VERSION 5.8 ;
BUSBITCHARS "[]" ;
DIVIDERCHAR "/" ;
CLEARANCEMEASURE EUCLIDEAN ;

SITE coresite
    SIZE 0.0450 BY 0.1440 ;
    CLASS CORE ;
    SYMMETRY X Y ;
END coresite

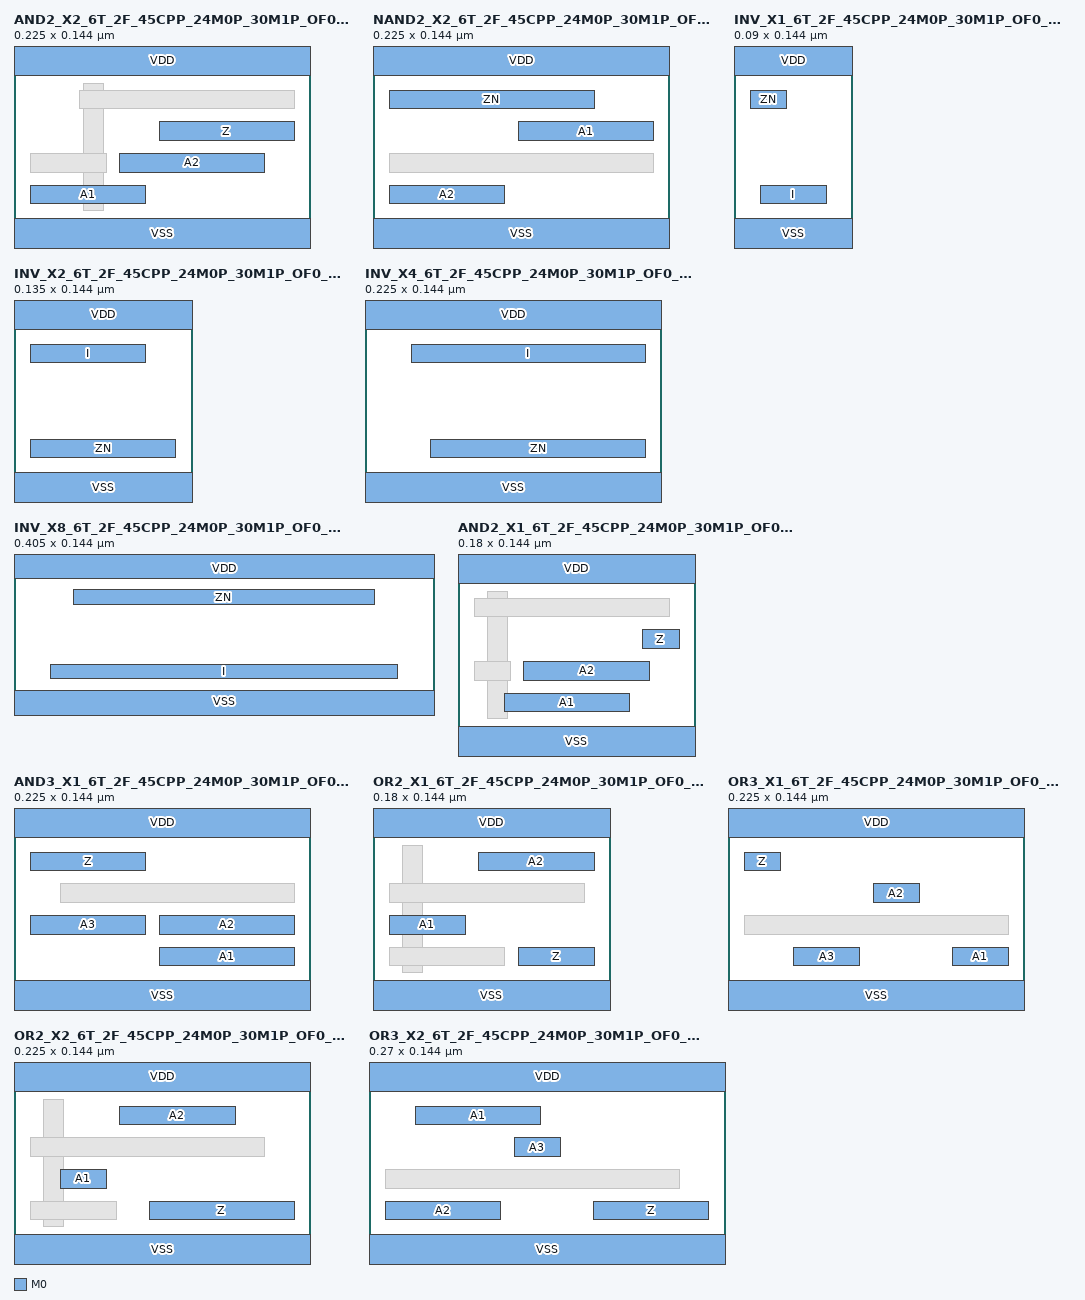
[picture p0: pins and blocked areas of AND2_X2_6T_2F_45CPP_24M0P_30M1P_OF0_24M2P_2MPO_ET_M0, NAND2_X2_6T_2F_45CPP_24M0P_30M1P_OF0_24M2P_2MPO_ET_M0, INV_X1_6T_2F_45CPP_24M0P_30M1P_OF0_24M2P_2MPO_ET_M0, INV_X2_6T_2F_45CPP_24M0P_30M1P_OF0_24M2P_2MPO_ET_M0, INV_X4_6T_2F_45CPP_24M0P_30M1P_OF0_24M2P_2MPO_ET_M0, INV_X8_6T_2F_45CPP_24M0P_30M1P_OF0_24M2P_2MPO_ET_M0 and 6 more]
MACRO AND2_X2_6T_2F_45CPP_24M0P_30M1P_OF0_24M2P_2MPO_ET_M0
  CLASS CORE ;
  ORIGIN 0 0 ;
  FOREIGN AND2_X2_6T_2F_45CPP_24M0P_30M1P_OF0_24M2P_2MPO_ET_M0 0 0 ;
  SIZE 0.2250 BY 0.1440 ;
  SYMMETRY X Y ;
  SITE coresite ;
  PIN A2
    DIRECTION INPUT ;
    USE SIGNAL ;
    PORT
      LAYER M0 ;
        RECT 0.0800 0.0670 0.1900 0.0530 ;
    END
  END A2
  PIN A1
    DIRECTION INPUT ;
    USE SIGNAL ;
    PORT
      LAYER M0 ;
        RECT 0.0125 0.0430 0.1000 0.0290 ;
    END
  END A1
  PIN Z
    DIRECTION OUTPUT ;
    USE SIGNAL ;
    PORT
      LAYER M0 ;
        RECT 0.1100 0.0910 0.2125 0.0770 ;
    END
  END Z
  PIN VDD
    DIRECTION INOUT ;
    USE POWER ;
    SHAPE ABUTMENT ;
    PORT
      LAYER M0 ;
        RECT 0.0000 0.1260 0.2250 0.1620 ;
    END
  END VDD
  PIN VSS
    DIRECTION INOUT ;
    USE GROUND ;
    SHAPE ABUTMENT ;
    PORT
      LAYER M0 ;
        RECT 0.0000 -0.0180 0.2250 0.0180 ;
    END
  END VSS
  OBS
      LAYER V0 ;
        RECT 0.0530 0.0530 0.0670 0.0670 ;
        RECT 0.0530 0.1010 0.0670 0.1150 ;
      LAYER M1 ;
        RECT 0.0525 0.1200 0.0675 0.0240 ;
      LAYER M0 ;
        RECT 0.0500 0.1010 0.2125 0.1150 ;
        RECT 0.0125 0.0530 0.0700 0.0670 ;
  END
END AND2_X2_6T_2F_45CPP_24M0P_30M1P_OF0_24M2P_2MPO_ET_M0

MACRO NAND2_X2_6T_2F_45CPP_24M0P_30M1P_OF0_24M2P_2MPO_ET_M0
  CLASS CORE ;
  ORIGIN 0 0 ;
  FOREIGN NAND2_X2_6T_2F_45CPP_24M0P_30M1P_OF0_24M2P_2MPO_ET_M0 0 0 ;
  SIZE 0.2250 BY 0.1440 ;
  SYMMETRY X Y ;
  SITE coresite ;
  PIN ZN
    DIRECTION OUTPUT ;
    USE SIGNAL ;
    PORT
      LAYER M0 ;
        RECT 0.0125 0.1150 0.1675 0.1010 ;
    END
  END ZN
  PIN A2
    DIRECTION INPUT ;
    USE SIGNAL ;
    PORT
      LAYER M0 ;
        RECT 0.0125 0.0430 0.1000 0.0290 ;
    END
  END A2
  PIN A1
    DIRECTION INPUT ;
    USE SIGNAL ;
    PORT
      LAYER M0 ;
        RECT 0.1100 0.0910 0.2125 0.0770 ;
    END
  END A1
  PIN VDD
    DIRECTION INOUT ;
    USE POWER ;
    SHAPE ABUTMENT ;
    PORT
      LAYER M0 ;
        RECT 0.0000 0.1260 0.2250 0.1620 ;
    END
  END VDD
  PIN VSS
    DIRECTION INOUT ;
    USE GROUND ;
    SHAPE ABUTMENT ;
    PORT
      LAYER M0 ;
        RECT 0.0000 -0.0180 0.2250 0.0180 ;
    END
  END VSS
  OBS
      LAYER M0 ;
        RECT 0.0125 0.0530 0.2125 0.0670 ;
  END
END NAND2_X2_6T_2F_45CPP_24M0P_30M1P_OF0_24M2P_2MPO_ET_M0

MACRO INV_X1_6T_2F_45CPP_24M0P_30M1P_OF0_24M2P_2MPO_ET_M0
  CLASS CORE ;
  ORIGIN 0 0 ;
  FOREIGN INV_X1_6T_2F_45CPP_24M0P_30M1P_OF0_24M2P_2MPO_ET_M0 0 0 ;
  SIZE 0.0900 BY 0.1440 ;
  SYMMETRY X Y ;
  SITE coresite ;
  PIN ZN
    DIRECTION OUTPUT ;
    USE SIGNAL ;
    PORT
      LAYER M0 ;
        RECT 0.0125 0.1150 0.0400 0.1010 ;
    END
  END ZN
  PIN I
    DIRECTION INPUT ;
    USE SIGNAL ;
    PORT
      LAYER M0 ;
        RECT 0.0200 0.0430 0.0700 0.0290 ;
    END
  END I
  PIN VDD
    DIRECTION INOUT ;
    USE POWER ;
    SHAPE ABUTMENT ;
    PORT
      LAYER M0 ;
        RECT 0.0000 0.1260 0.0900 0.1620 ;
    END
  END VDD
  PIN VSS
    DIRECTION INOUT ;
    USE GROUND ;
    SHAPE ABUTMENT ;
    PORT
      LAYER M0 ;
        RECT 0.0000 -0.0180 0.0900 0.0180 ;
    END
  END VSS
END INV_X1_6T_2F_45CPP_24M0P_30M1P_OF0_24M2P_2MPO_ET_M0

MACRO INV_X2_6T_2F_45CPP_24M0P_30M1P_OF0_24M2P_2MPO_ET_M0
  CLASS CORE ;
  ORIGIN 0 0 ;
  FOREIGN INV_X2_6T_2F_45CPP_24M0P_30M1P_OF0_24M2P_2MPO_ET_M0 0 0 ;
  SIZE 0.1350 BY 0.1440 ;
  SYMMETRY X Y ;
  SITE coresite ;
  PIN I
    DIRECTION INPUT ;
    USE SIGNAL ;
    PORT
      LAYER M0 ;
        RECT 0.0125 0.1150 0.1000 0.1010 ;
    END
  END I
  PIN ZN
    DIRECTION OUTPUT ;
    USE SIGNAL ;
    PORT
      LAYER M0 ;
        RECT 0.0125 0.0430 0.1225 0.0290 ;
    END
  END ZN
  PIN VDD
    DIRECTION INOUT ;
    USE POWER ;
    SHAPE ABUTMENT ;
    PORT
      LAYER M0 ;
        RECT 0.0000 0.1260 0.1350 0.1620 ;
    END
  END VDD
  PIN VSS
    DIRECTION INOUT ;
    USE GROUND ;
    SHAPE ABUTMENT ;
    PORT
      LAYER M0 ;
        RECT 0.0000 -0.0180 0.1350 0.0180 ;
    END
  END VSS
END INV_X2_6T_2F_45CPP_24M0P_30M1P_OF0_24M2P_2MPO_ET_M0

MACRO INV_X4_6T_2F_45CPP_24M0P_30M1P_OF0_24M2P_2MPO_ET_M0
  CLASS CORE ;
  ORIGIN 0 0 ;
  FOREIGN INV_X4_6T_2F_45CPP_24M0P_30M1P_OF0_24M2P_2MPO_ET_M0 0 0 ;
  SIZE 0.2250 BY 0.1440 ;
  SYMMETRY X Y ;
  SITE coresite ;
  PIN I
    DIRECTION INPUT ;
    USE SIGNAL ;
    PORT
      LAYER M0 ;
        RECT 0.0350 0.1150 0.2125 0.1010 ;
    END
  END I
  PIN ZN
    DIRECTION OUTPUT ;
    USE SIGNAL ;
    PORT
      LAYER M0 ;
        RECT 0.0500 0.0430 0.2125 0.0290 ;
    END
  END ZN
  PIN VDD
    DIRECTION INOUT ;
    USE POWER ;
    SHAPE ABUTMENT ;
    PORT
      LAYER M0 ;
        RECT 0.0000 0.1260 0.2250 0.1620 ;
    END
  END VDD
  PIN VSS
    DIRECTION INOUT ;
    USE GROUND ;
    SHAPE ABUTMENT ;
    PORT
      LAYER M0 ;
        RECT 0.0000 -0.0180 0.2250 0.0180 ;
    END
  END VSS
END INV_X4_6T_2F_45CPP_24M0P_30M1P_OF0_24M2P_2MPO_ET_M0

MACRO INV_X8_6T_2F_45CPP_24M0P_30M1P_OF0_24M2P_2MPO_ET_M0
  CLASS CORE ;
  ORIGIN 0 0 ;
  FOREIGN INV_X8_6T_2F_45CPP_24M0P_30M1P_OF0_24M2P_2MPO_ET_M0 0 0 ;
  SIZE 0.4050 BY 0.1440 ;
  SYMMETRY X Y ;
  SITE coresite ;
  PIN ZN
    DIRECTION OUTPUT ;
    USE SIGNAL ;
    PORT
      LAYER M0 ;
        RECT 0.0575 0.1150 0.3475 0.1010 ;
    END
  END ZN
  PIN I
    DIRECTION INPUT ;
    USE SIGNAL ;
    PORT
      LAYER M0 ;
        RECT 0.0350 0.0430 0.3700 0.0290 ;
    END
  END I
  PIN VDD
    DIRECTION INOUT ;
    USE POWER ;
    SHAPE ABUTMENT ;
    PORT
      LAYER M0 ;
        RECT 0.0000 0.1260 0.4050 0.1620 ;
    END
  END VDD
  PIN VSS
    DIRECTION INOUT ;
    USE GROUND ;
    SHAPE ABUTMENT ;
    PORT
      LAYER M0 ;
        RECT 0.0000 -0.0180 0.4050 0.0180 ;
    END
  END VSS
END INV_X8_6T_2F_45CPP_24M0P_30M1P_OF0_24M2P_2MPO_ET_M0

MACRO AND2_X1_6T_2F_45CPP_24M0P_30M1P_OF0_24M2P_2MPO_ET_M0
  CLASS CORE ;
  ORIGIN 0 0 ;
  FOREIGN AND2_X1_6T_2F_45CPP_24M0P_30M1P_OF0_24M2P_2MPO_ET_M0 0 0 ;
  SIZE 0.1800 BY 0.1440 ;
  SYMMETRY X Y ;
  SITE coresite ;
  PIN A2
    DIRECTION INPUT ;
    USE SIGNAL ;
    PORT
      LAYER M0 ;
        RECT 0.0500 0.0670 0.1450 0.0530 ;
    END
  END A2
  PIN A1
    DIRECTION INPUT ;
    USE SIGNAL ;
    PORT
      LAYER M0 ;
        RECT 0.0350 0.0430 0.1300 0.0290 ;
    END
  END A1
  PIN Z
    DIRECTION OUTPUT ;
    USE SIGNAL ;
    PORT
      LAYER M0 ;
        RECT 0.1400 0.0910 0.1675 0.0770 ;
    END
  END Z
  PIN VDD
    DIRECTION INOUT ;
    USE POWER ;
    SHAPE ABUTMENT ;
    PORT
      LAYER M0 ;
        RECT 0.0000 0.1260 0.1800 0.1620 ;
    END
  END VDD
  PIN VSS
    DIRECTION INOUT ;
    USE GROUND ;
    SHAPE ABUTMENT ;
    PORT
      LAYER M0 ;
        RECT 0.0000 -0.0180 0.1800 0.0180 ;
    END
  END VSS
  OBS
      LAYER V0 ;
        RECT 0.0230 0.0530 0.0370 0.0670 ;
        RECT 0.0230 0.1010 0.0370 0.1150 ;
      LAYER M1 ;
        RECT 0.0225 0.1200 0.0375 0.0240 ;
      LAYER M0 ;
        RECT 0.0125 0.1010 0.1600 0.1150 ;
        RECT 0.0125 0.0530 0.0400 0.0670 ;
  END
END AND2_X1_6T_2F_45CPP_24M0P_30M1P_OF0_24M2P_2MPO_ET_M0

MACRO AND3_X1_6T_2F_45CPP_24M0P_30M1P_OF0_24M2P_2MPO_ET_M0
  CLASS CORE ;
  ORIGIN 0 0 ;
  FOREIGN AND3_X1_6T_2F_45CPP_24M0P_30M1P_OF0_24M2P_2MPO_ET_M0 0 0 ;
  SIZE 0.2250 BY 0.1440 ;
  SYMMETRY X Y ;
  SITE coresite ;
  PIN A3
    DIRECTION INPUT ;
    USE SIGNAL ;
    PORT
      LAYER M0 ;
        RECT 0.0125 0.0670 0.1000 0.0530 ;
    END
  END A3
  PIN A2
    DIRECTION INPUT ;
    USE SIGNAL ;
    PORT
      LAYER M0 ;
        RECT 0.1100 0.0670 0.2125 0.0530 ;
    END
  END A2
  PIN Z
    DIRECTION OUTPUT ;
    USE SIGNAL ;
    PORT
      LAYER M0 ;
        RECT 0.0125 0.1150 0.1000 0.1010 ;
    END
  END Z
  PIN A1
    DIRECTION INPUT ;
    USE SIGNAL ;
    PORT
      LAYER M0 ;
        RECT 0.1100 0.0430 0.2125 0.0290 ;
    END
  END A1
  PIN VDD
    DIRECTION INOUT ;
    USE POWER ;
    SHAPE ABUTMENT ;
    PORT
      LAYER M0 ;
        RECT 0.0000 0.1260 0.2250 0.1620 ;
    END
  END VDD
  PIN VSS
    DIRECTION INOUT ;
    USE GROUND ;
    SHAPE ABUTMENT ;
    PORT
      LAYER M0 ;
        RECT 0.0000 -0.0180 0.2250 0.0180 ;
    END
  END VSS
  OBS
      LAYER M0 ;
        RECT 0.0350 0.0770 0.2125 0.0910 ;
  END
END AND3_X1_6T_2F_45CPP_24M0P_30M1P_OF0_24M2P_2MPO_ET_M0

MACRO OR2_X1_6T_2F_45CPP_24M0P_30M1P_OF0_24M2P_2MPO_ET_M0
  CLASS CORE ;
  ORIGIN 0 0 ;
  FOREIGN OR2_X1_6T_2F_45CPP_24M0P_30M1P_OF0_24M2P_2MPO_ET_M0 0 0 ;
  SIZE 0.1800 BY 0.1440 ;
  SYMMETRY X Y ;
  SITE coresite ;
  PIN A1
    DIRECTION INPUT ;
    USE SIGNAL ;
    PORT
      LAYER M0 ;
        RECT 0.0125 0.0670 0.0700 0.0530 ;
    END
  END A1
  PIN A2
    DIRECTION INPUT ;
    USE SIGNAL ;
    PORT
      LAYER M0 ;
        RECT 0.0800 0.1150 0.1675 0.1010 ;
    END
  END A2
  PIN Z
    DIRECTION OUTPUT ;
    USE SIGNAL ;
    PORT
      LAYER M0 ;
        RECT 0.1100 0.0430 0.1675 0.0290 ;
    END
  END Z
  PIN VDD
    DIRECTION INOUT ;
    USE POWER ;
    SHAPE ABUTMENT ;
    PORT
      LAYER M0 ;
        RECT 0.0000 0.1260 0.1800 0.1620 ;
    END
  END VDD
  PIN VSS
    DIRECTION INOUT ;
    USE GROUND ;
    SHAPE ABUTMENT ;
    PORT
      LAYER M0 ;
        RECT 0.0000 -0.0180 0.1800 0.0180 ;
    END
  END VSS
  OBS
      LAYER V0 ;
        RECT 0.0230 0.0290 0.0370 0.0430 ;
        RECT 0.0230 0.0770 0.0370 0.0910 ;
      LAYER M1 ;
        RECT 0.0225 0.1200 0.0375 0.0240 ;
      LAYER M0 ;
        RECT 0.0125 0.0770 0.1600 0.0910 ;
        RECT 0.0125 0.0290 0.1000 0.0430 ;
  END
END OR2_X1_6T_2F_45CPP_24M0P_30M1P_OF0_24M2P_2MPO_ET_M0

MACRO OR3_X1_6T_2F_45CPP_24M0P_30M1P_OF0_24M2P_2MPO_ET_M0
  CLASS CORE ;
  ORIGIN 0 0 ;
  FOREIGN OR3_X1_6T_2F_45CPP_24M0P_30M1P_OF0_24M2P_2MPO_ET_M0 0 0 ;
  SIZE 0.2250 BY 0.1440 ;
  SYMMETRY X Y ;
  SITE coresite ;
  PIN Z
    DIRECTION OUTPUT ;
    USE SIGNAL ;
    PORT
      LAYER M0 ;
        RECT 0.0125 0.1150 0.0400 0.1010 ;
    END
  END Z
  PIN A3
    DIRECTION INPUT ;
    USE SIGNAL ;
    PORT
      LAYER M0 ;
        RECT 0.0500 0.0430 0.1000 0.0290 ;
    END
  END A3
  PIN A2
    DIRECTION INPUT ;
    USE SIGNAL ;
    PORT
      LAYER M0 ;
        RECT 0.1100 0.0910 0.1450 0.0770 ;
    END
  END A2
  PIN A1
    DIRECTION INPUT ;
    USE SIGNAL ;
    PORT
      LAYER M0 ;
        RECT 0.1700 0.0430 0.2125 0.0290 ;
    END
  END A1
  PIN VDD
    DIRECTION INOUT ;
    USE POWER ;
    SHAPE ABUTMENT ;
    PORT
      LAYER M0 ;
        RECT 0.0000 0.1260 0.2250 0.1620 ;
    END
  END VDD
  PIN VSS
    DIRECTION INOUT ;
    USE GROUND ;
    SHAPE ABUTMENT ;
    PORT
      LAYER M0 ;
        RECT 0.0000 -0.0180 0.2250 0.0180 ;
    END
  END VSS
  OBS
      LAYER M0 ;
        RECT 0.0125 0.0530 0.2125 0.0670 ;
  END
END OR3_X1_6T_2F_45CPP_24M0P_30M1P_OF0_24M2P_2MPO_ET_M0

MACRO OR2_X2_6T_2F_45CPP_24M0P_30M1P_OF0_24M2P_2MPO_ET_M0
  CLASS CORE ;
  ORIGIN 0 0 ;
  FOREIGN OR2_X2_6T_2F_45CPP_24M0P_30M1P_OF0_24M2P_2MPO_ET_M0 0 0 ;
  SIZE 0.2250 BY 0.1440 ;
  SYMMETRY X Y ;
  SITE coresite ;
  PIN A1
    DIRECTION INPUT ;
    USE SIGNAL ;
    PORT
      LAYER M0 ;
        RECT 0.0350 0.0670 0.0700 0.0530 ;
    END
  END A1
  PIN A2
    DIRECTION INPUT ;
    USE SIGNAL ;
    PORT
      LAYER M0 ;
        RECT 0.0800 0.1150 0.1675 0.1010 ;
    END
  END A2
  PIN Z
    DIRECTION OUTPUT ;
    USE SIGNAL ;
    PORT
      LAYER M0 ;
        RECT 0.1025 0.0430 0.2125 0.0290 ;
    END
  END Z
  PIN VDD
    DIRECTION INOUT ;
    USE POWER ;
    SHAPE ABUTMENT ;
    PORT
      LAYER M0 ;
        RECT 0.0000 0.1260 0.2250 0.1620 ;
    END
  END VDD
  PIN VSS
    DIRECTION INOUT ;
    USE GROUND ;
    SHAPE ABUTMENT ;
    PORT
      LAYER M0 ;
        RECT 0.0000 -0.0180 0.2250 0.0180 ;
    END
  END VSS
  OBS
      LAYER V0 ;
        RECT 0.0230 0.0290 0.0370 0.0430 ;
        RECT 0.0230 0.0770 0.0370 0.0910 ;
      LAYER M1 ;
        RECT 0.0225 0.1200 0.0375 0.0240 ;
      LAYER M0 ;
        RECT 0.0125 0.0770 0.1900 0.0910 ;
        RECT 0.0125 0.0290 0.0775 0.0430 ;
  END
END OR2_X2_6T_2F_45CPP_24M0P_30M1P_OF0_24M2P_2MPO_ET_M0

MACRO OR3_X2_6T_2F_45CPP_24M0P_30M1P_OF0_24M2P_2MPO_ET_M0
  CLASS CORE ;
  ORIGIN 0 0 ;
  FOREIGN OR3_X2_6T_2F_45CPP_24M0P_30M1P_OF0_24M2P_2MPO_ET_M0 0 0 ;
  SIZE 0.2700 BY 0.1440 ;
  SYMMETRY X Y ;
  SITE coresite ;
  PIN A1
    DIRECTION INPUT ;
    USE SIGNAL ;
    PORT
      LAYER M0 ;
        RECT 0.0350 0.1150 0.1300 0.1010 ;
    END
  END A1
  PIN A2
    DIRECTION INPUT ;
    USE SIGNAL ;
    PORT
      LAYER M0 ;
        RECT 0.0125 0.0430 0.1000 0.0290 ;
    END
  END A2
  PIN A3
    DIRECTION INPUT ;
    USE SIGNAL ;
    PORT
      LAYER M0 ;
        RECT 0.1100 0.0910 0.1450 0.0770 ;
    END
  END A3
  PIN Z
    DIRECTION OUTPUT ;
    USE SIGNAL ;
    PORT
      LAYER M0 ;
        RECT 0.1700 0.0430 0.2575 0.0290 ;
    END
  END Z
  PIN VDD
    DIRECTION INOUT ;
    USE POWER ;
    SHAPE ABUTMENT ;
    PORT
      LAYER M0 ;
        RECT 0.0000 0.1260 0.2700 0.1620 ;
    END
  END VDD
  PIN VSS
    DIRECTION INOUT ;
    USE GROUND ;
    SHAPE ABUTMENT ;
    PORT
      LAYER M0 ;
        RECT 0.0000 -0.0180 0.2700 0.0180 ;
    END
  END VSS
  OBS
      LAYER M0 ;
        RECT 0.0125 0.0530 0.2350 0.0670 ;
  END
END OR3_X2_6T_2F_45CPP_24M0P_30M1P_OF0_24M2P_2MPO_ET_M0

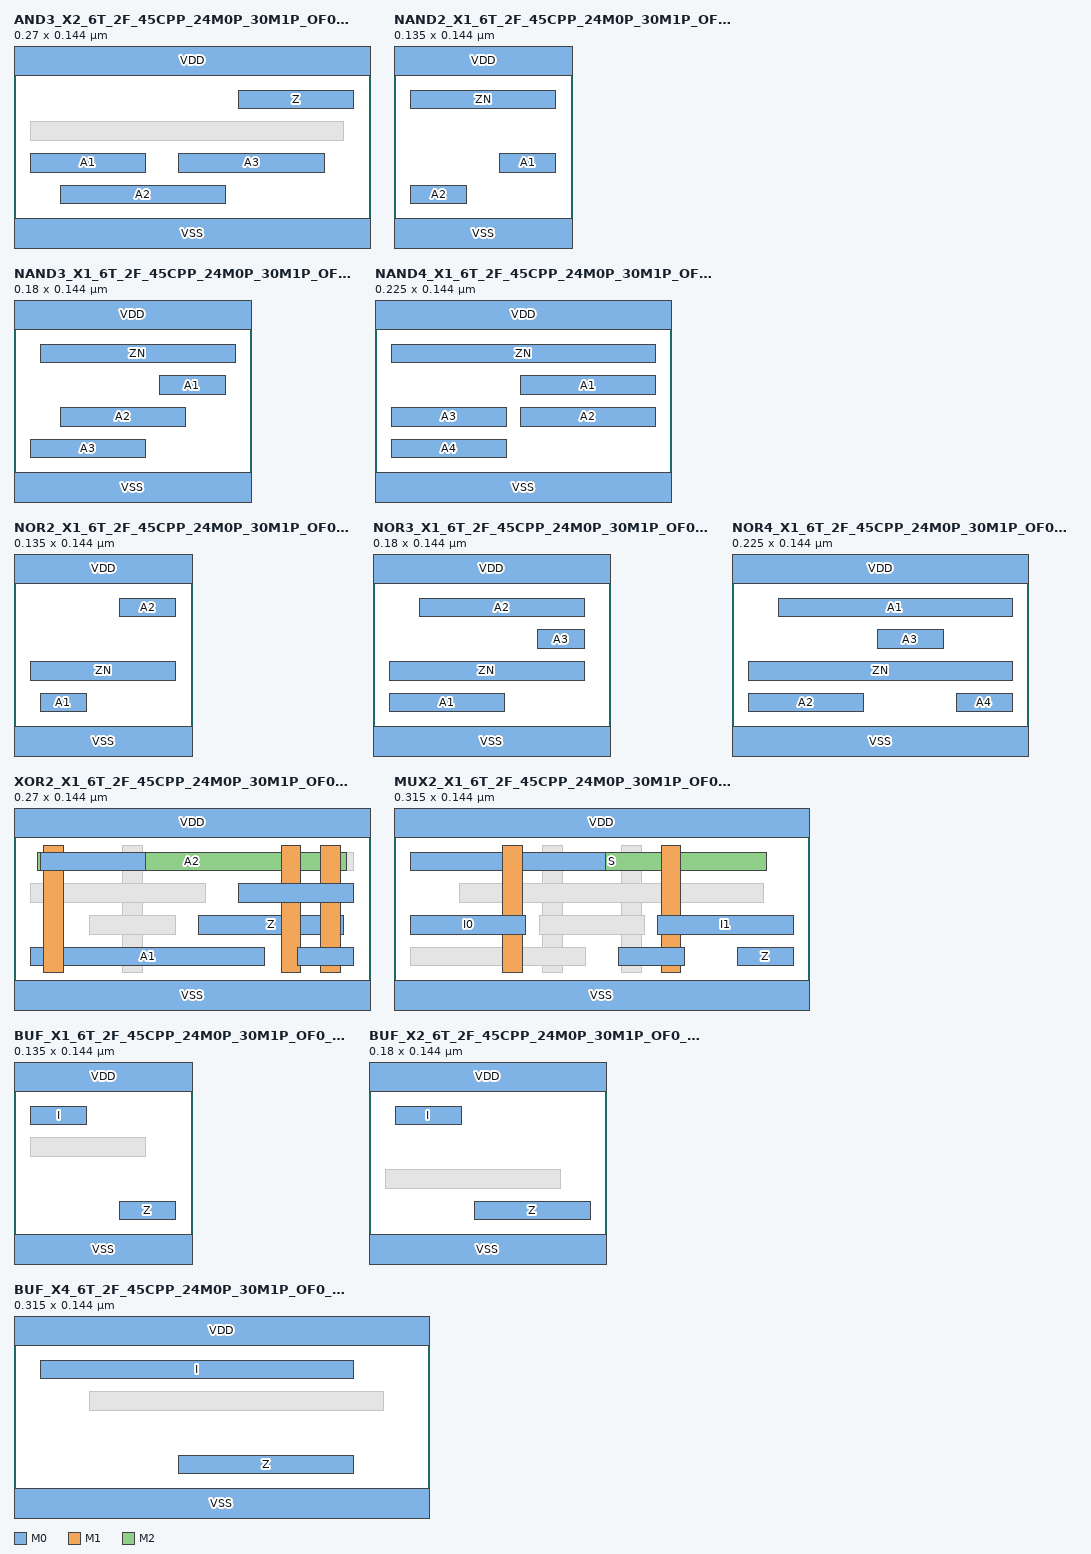
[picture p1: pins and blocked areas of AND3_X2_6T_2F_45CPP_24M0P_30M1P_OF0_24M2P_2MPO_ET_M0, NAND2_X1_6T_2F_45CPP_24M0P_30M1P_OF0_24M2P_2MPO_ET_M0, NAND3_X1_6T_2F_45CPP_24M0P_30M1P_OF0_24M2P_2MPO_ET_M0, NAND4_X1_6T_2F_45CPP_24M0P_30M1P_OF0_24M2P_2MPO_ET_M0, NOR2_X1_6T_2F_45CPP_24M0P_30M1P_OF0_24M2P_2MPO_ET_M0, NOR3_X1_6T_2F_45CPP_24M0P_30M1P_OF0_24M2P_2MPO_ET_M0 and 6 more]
MACRO AND3_X2_6T_2F_45CPP_24M0P_30M1P_OF0_24M2P_2MPO_ET_M0
  CLASS CORE ;
  ORIGIN 0 0 ;
  FOREIGN AND3_X2_6T_2F_45CPP_24M0P_30M1P_OF0_24M2P_2MPO_ET_M0 0 0 ;
  SIZE 0.2700 BY 0.1440 ;
  SYMMETRY X Y ;
  SITE coresite ;
  PIN A1
    DIRECTION INPUT ;
    USE SIGNAL ;
    PORT
      LAYER M0 ;
        RECT 0.0125 0.0670 0.1000 0.0530 ;
    END
  END A1
  PIN A3
    DIRECTION INPUT ;
    USE SIGNAL ;
    PORT
      LAYER M0 ;
        RECT 0.1250 0.0670 0.2350 0.0530 ;
    END
  END A3
  PIN A2
    DIRECTION INPUT ;
    USE SIGNAL ;
    PORT
      LAYER M0 ;
        RECT 0.0350 0.0430 0.1600 0.0290 ;
    END
  END A2
  PIN Z
    DIRECTION OUTPUT ;
    USE SIGNAL ;
    PORT
      LAYER M0 ;
        RECT 0.1700 0.1150 0.2575 0.1010 ;
    END
  END Z
  PIN VDD
    DIRECTION INOUT ;
    USE POWER ;
    SHAPE ABUTMENT ;
    PORT
      LAYER M0 ;
        RECT 0.0000 0.1260 0.2700 0.1620 ;
    END
  END VDD
  PIN VSS
    DIRECTION INOUT ;
    USE GROUND ;
    SHAPE ABUTMENT ;
    PORT
      LAYER M0 ;
        RECT 0.0000 -0.0180 0.2700 0.0180 ;
    END
  END VSS
  OBS
      LAYER M0 ;
        RECT 0.0125 0.0770 0.2500 0.0910 ;
  END
END AND3_X2_6T_2F_45CPP_24M0P_30M1P_OF0_24M2P_2MPO_ET_M0

MACRO NAND2_X1_6T_2F_45CPP_24M0P_30M1P_OF0_24M2P_2MPO_ET_M0
  CLASS CORE ;
  ORIGIN 0 0 ;
  FOREIGN NAND2_X1_6T_2F_45CPP_24M0P_30M1P_OF0_24M2P_2MPO_ET_M0 0 0 ;
  SIZE 0.1350 BY 0.1440 ;
  SYMMETRY X Y ;
  SITE coresite ;
  PIN ZN
    DIRECTION OUTPUT ;
    USE SIGNAL ;
    PORT
      LAYER M0 ;
        RECT 0.0125 0.1150 0.1225 0.1010 ;
    END
  END ZN
  PIN A2
    DIRECTION INPUT ;
    USE SIGNAL ;
    PORT
      LAYER M0 ;
        RECT 0.0125 0.0430 0.0550 0.0290 ;
    END
  END A2
  PIN A1
    DIRECTION INPUT ;
    USE SIGNAL ;
    PORT
      LAYER M0 ;
        RECT 0.0800 0.0670 0.1225 0.0530 ;
    END
  END A1
  PIN VDD
    DIRECTION INOUT ;
    USE POWER ;
    SHAPE ABUTMENT ;
    PORT
      LAYER M0 ;
        RECT 0.0000 0.1260 0.1350 0.1620 ;
    END
  END VDD
  PIN VSS
    DIRECTION INOUT ;
    USE GROUND ;
    SHAPE ABUTMENT ;
    PORT
      LAYER M0 ;
        RECT 0.0000 -0.0180 0.1350 0.0180 ;
    END
  END VSS
END NAND2_X1_6T_2F_45CPP_24M0P_30M1P_OF0_24M2P_2MPO_ET_M0

MACRO NAND3_X1_6T_2F_45CPP_24M0P_30M1P_OF0_24M2P_2MPO_ET_M0
  CLASS CORE ;
  ORIGIN 0 0 ;
  FOREIGN NAND3_X1_6T_2F_45CPP_24M0P_30M1P_OF0_24M2P_2MPO_ET_M0 0 0 ;
  SIZE 0.1800 BY 0.1440 ;
  SYMMETRY X Y ;
  SITE coresite ;
  PIN ZN
    DIRECTION OUTPUT ;
    USE SIGNAL ;
    PORT
      LAYER M0 ;
        RECT 0.0200 0.1150 0.1675 0.1010 ;
    END
  END ZN
  PIN A2
    DIRECTION INPUT ;
    USE SIGNAL ;
    PORT
      LAYER M0 ;
        RECT 0.0350 0.0670 0.1300 0.0530 ;
    END
  END A2
  PIN A3
    DIRECTION INPUT ;
    USE SIGNAL ;
    PORT
      LAYER M0 ;
        RECT 0.0125 0.0430 0.1000 0.0290 ;
    END
  END A3
  PIN A1
    DIRECTION INPUT ;
    USE SIGNAL ;
    PORT
      LAYER M0 ;
        RECT 0.1100 0.0910 0.1600 0.0770 ;
    END
  END A1
  PIN VDD
    DIRECTION INOUT ;
    USE POWER ;
    SHAPE ABUTMENT ;
    PORT
      LAYER M0 ;
        RECT 0.0000 0.1260 0.1800 0.1620 ;
    END
  END VDD
  PIN VSS
    DIRECTION INOUT ;
    USE GROUND ;
    SHAPE ABUTMENT ;
    PORT
      LAYER M0 ;
        RECT 0.0000 -0.0180 0.1800 0.0180 ;
    END
  END VSS
END NAND3_X1_6T_2F_45CPP_24M0P_30M1P_OF0_24M2P_2MPO_ET_M0

MACRO NAND4_X1_6T_2F_45CPP_24M0P_30M1P_OF0_24M2P_2MPO_ET_M0
  CLASS CORE ;
  ORIGIN 0 0 ;
  FOREIGN NAND4_X1_6T_2F_45CPP_24M0P_30M1P_OF0_24M2P_2MPO_ET_M0 0 0 ;
  SIZE 0.2250 BY 0.1440 ;
  SYMMETRY X Y ;
  SITE coresite ;
  PIN ZN
    DIRECTION OUTPUT ;
    USE SIGNAL ;
    PORT
      LAYER M0 ;
        RECT 0.0125 0.1150 0.2125 0.1010 ;
    END
  END ZN
  PIN A3
    DIRECTION INPUT ;
    USE SIGNAL ;
    PORT
      LAYER M0 ;
        RECT 0.0125 0.0670 0.1000 0.0530 ;
    END
  END A3
  PIN A2
    DIRECTION INPUT ;
    USE SIGNAL ;
    PORT
      LAYER M0 ;
        RECT 0.1100 0.0670 0.2125 0.0530 ;
    END
  END A2
  PIN A4
    DIRECTION INPUT ;
    USE SIGNAL ;
    PORT
      LAYER M0 ;
        RECT 0.0125 0.0430 0.1000 0.0290 ;
    END
  END A4
  PIN A1
    DIRECTION INPUT ;
    USE SIGNAL ;
    PORT
      LAYER M0 ;
        RECT 0.1100 0.0910 0.2125 0.0770 ;
    END
  END A1
  PIN VDD
    DIRECTION INOUT ;
    USE POWER ;
    SHAPE ABUTMENT ;
    PORT
      LAYER M0 ;
        RECT 0.0000 0.1260 0.2250 0.1620 ;
    END
  END VDD
  PIN VSS
    DIRECTION INOUT ;
    USE GROUND ;
    SHAPE ABUTMENT ;
    PORT
      LAYER M0 ;
        RECT 0.0000 -0.0180 0.2250 0.0180 ;
    END
  END VSS
END NAND4_X1_6T_2F_45CPP_24M0P_30M1P_OF0_24M2P_2MPO_ET_M0

MACRO NOR2_X1_6T_2F_45CPP_24M0P_30M1P_OF0_24M2P_2MPO_ET_M0
  CLASS CORE ;
  ORIGIN 0 0 ;
  FOREIGN NOR2_X1_6T_2F_45CPP_24M0P_30M1P_OF0_24M2P_2MPO_ET_M0 0 0 ;
  SIZE 0.1350 BY 0.1440 ;
  SYMMETRY X Y ;
  SITE coresite ;
  PIN ZN
    DIRECTION OUTPUT ;
    USE SIGNAL ;
    PORT
      LAYER M0 ;
        RECT 0.0125 0.0670 0.1225 0.0530 ;
    END
  END ZN
  PIN A1
    DIRECTION INPUT ;
    USE SIGNAL ;
    PORT
      LAYER M0 ;
        RECT 0.0200 0.0430 0.0550 0.0290 ;
    END
  END A1
  PIN A2
    DIRECTION INPUT ;
    USE SIGNAL ;
    PORT
      LAYER M0 ;
        RECT 0.0800 0.1150 0.1225 0.1010 ;
    END
  END A2
  PIN VDD
    DIRECTION INOUT ;
    USE POWER ;
    SHAPE ABUTMENT ;
    PORT
      LAYER M0 ;
        RECT 0.0000 0.1260 0.1350 0.1620 ;
    END
  END VDD
  PIN VSS
    DIRECTION INOUT ;
    USE GROUND ;
    SHAPE ABUTMENT ;
    PORT
      LAYER M0 ;
        RECT 0.0000 -0.0180 0.1350 0.0180 ;
    END
  END VSS
END NOR2_X1_6T_2F_45CPP_24M0P_30M1P_OF0_24M2P_2MPO_ET_M0

MACRO NOR3_X1_6T_2F_45CPP_24M0P_30M1P_OF0_24M2P_2MPO_ET_M0
  CLASS CORE ;
  ORIGIN 0 0 ;
  FOREIGN NOR3_X1_6T_2F_45CPP_24M0P_30M1P_OF0_24M2P_2MPO_ET_M0 0 0 ;
  SIZE 0.1800 BY 0.1440 ;
  SYMMETRY X Y ;
  SITE coresite ;
  PIN A2
    DIRECTION INPUT ;
    USE SIGNAL ;
    PORT
      LAYER M0 ;
        RECT 0.0350 0.1150 0.1600 0.1010 ;
    END
  END A2
  PIN ZN
    DIRECTION OUTPUT ;
    USE SIGNAL ;
    PORT
      LAYER M0 ;
        RECT 0.0125 0.0670 0.1600 0.0530 ;
    END
  END ZN
  PIN A1
    DIRECTION INPUT ;
    USE SIGNAL ;
    PORT
      LAYER M0 ;
        RECT 0.0125 0.0430 0.1000 0.0290 ;
    END
  END A1
  PIN A3
    DIRECTION INPUT ;
    USE SIGNAL ;
    PORT
      LAYER M0 ;
        RECT 0.1250 0.0910 0.1600 0.0770 ;
    END
  END A3
  PIN VDD
    DIRECTION INOUT ;
    USE POWER ;
    SHAPE ABUTMENT ;
    PORT
      LAYER M0 ;
        RECT 0.0000 0.1260 0.1800 0.1620 ;
    END
  END VDD
  PIN VSS
    DIRECTION INOUT ;
    USE GROUND ;
    SHAPE ABUTMENT ;
    PORT
      LAYER M0 ;
        RECT 0.0000 -0.0180 0.1800 0.0180 ;
    END
  END VSS
END NOR3_X1_6T_2F_45CPP_24M0P_30M1P_OF0_24M2P_2MPO_ET_M0

MACRO NOR4_X1_6T_2F_45CPP_24M0P_30M1P_OF0_24M2P_2MPO_ET_M0
  CLASS CORE ;
  ORIGIN 0 0 ;
  FOREIGN NOR4_X1_6T_2F_45CPP_24M0P_30M1P_OF0_24M2P_2MPO_ET_M0 0 0 ;
  SIZE 0.2250 BY 0.1440 ;
  SYMMETRY X Y ;
  SITE coresite ;
  PIN A1
    DIRECTION INPUT ;
    USE SIGNAL ;
    PORT
      LAYER M0 ;
        RECT 0.0350 0.1150 0.2125 0.1010 ;
    END
  END A1
  PIN ZN
    DIRECTION OUTPUT ;
    USE SIGNAL ;
    PORT
      LAYER M0 ;
        RECT 0.0125 0.0670 0.2125 0.0530 ;
    END
  END ZN
  PIN A2
    DIRECTION INPUT ;
    USE SIGNAL ;
    PORT
      LAYER M0 ;
        RECT 0.0125 0.0430 0.1000 0.0290 ;
    END
  END A2
  PIN A3
    DIRECTION INPUT ;
    USE SIGNAL ;
    PORT
      LAYER M0 ;
        RECT 0.1100 0.0910 0.1600 0.0770 ;
    END
  END A3
  PIN A4
    DIRECTION INPUT ;
    USE SIGNAL ;
    PORT
      LAYER M0 ;
        RECT 0.1700 0.0430 0.2125 0.0290 ;
    END
  END A4
  PIN VDD
    DIRECTION INOUT ;
    USE POWER ;
    SHAPE ABUTMENT ;
    PORT
      LAYER M0 ;
        RECT 0.0000 0.1260 0.2250 0.1620 ;
    END
  END VDD
  PIN VSS
    DIRECTION INOUT ;
    USE GROUND ;
    SHAPE ABUTMENT ;
    PORT
      LAYER M0 ;
        RECT 0.0000 -0.0180 0.2250 0.0180 ;
    END
  END VSS
END NOR4_X1_6T_2F_45CPP_24M0P_30M1P_OF0_24M2P_2MPO_ET_M0

MACRO XOR2_X1_6T_2F_45CPP_24M0P_30M1P_OF0_24M2P_2MPO_ET_M0
  CLASS CORE ;
  ORIGIN 0 0 ;
  FOREIGN XOR2_X1_6T_2F_45CPP_24M0P_30M1P_OF0_24M2P_2MPO_ET_M0 0 0 ;
  SIZE 0.2700 BY 0.1440 ;
  SYMMETRY X Y ;
  SITE coresite ;
  PIN Z
    DIRECTION OUTPUT ;
    USE SIGNAL ;
    PORT
      LAYER M1 ;
        RECT 0.2025 0.1200 0.2175 0.0240 ;
      LAYER M0 ;
        RECT 0.1700 0.0910 0.2575 0.0770 ;
        RECT 0.1400 0.0670 0.2500 0.0530 ;
    END
  END Z
  PIN A2
    DIRECTION INPUT ;
    USE SIGNAL ;
    PORT
      LAYER M2 ;
        RECT 0.0180 0.1150 0.2520 0.1010 ;
      LAYER M1 ;
        RECT 0.0225 0.1200 0.0375 0.0240 ;
        RECT 0.2325 0.1200 0.2475 0.0240 ;
      LAYER M0 ;
        RECT 0.0200 0.1150 0.1000 0.1010 ;
        RECT 0.2150 0.0430 0.2575 0.0290 ;
    END
  END A2
  PIN A1
    DIRECTION INPUT ;
    USE SIGNAL ;
    PORT
      LAYER M0 ;
        RECT 0.0125 0.0430 0.1900 0.0290 ;
    END
  END A1
  PIN VDD
    DIRECTION INOUT ;
    USE POWER ;
    SHAPE ABUTMENT ;
    PORT
      LAYER M0 ;
        RECT 0.0000 0.1260 0.2700 0.1620 ;
    END
  END VDD
  PIN VSS
    DIRECTION INOUT ;
    USE GROUND ;
    SHAPE ABUTMENT ;
    PORT
      LAYER M0 ;
        RECT 0.0000 -0.0180 0.2700 0.0180 ;
    END
  END VSS
  OBS
      LAYER V0 ;
        RECT 0.2330 0.0290 0.2470 0.0430 ;
        RECT 0.2030 0.0530 0.2170 0.0670 ;
        RECT 0.0830 0.0530 0.0970 0.0670 ;
        RECT 0.2030 0.0770 0.2170 0.0910 ;
        RECT 0.0830 0.0770 0.0970 0.0910 ;
        RECT 0.0230 0.1010 0.0370 0.1150 ;
      LAYER M1 ;
        RECT 0.0825 0.1200 0.0975 0.0240 ;
      LAYER M0 ;
        RECT 0.1100 0.1010 0.2575 0.1150 ;
        RECT 0.0125 0.0770 0.1450 0.0910 ;
        RECT 0.0575 0.0530 0.1225 0.0670 ;
      LAYER V1 ;
        RECT 0.2330 0.1010 0.2470 0.1150 ;
        RECT 0.0230 0.1010 0.0370 0.1150 ;
  END
END XOR2_X1_6T_2F_45CPP_24M0P_30M1P_OF0_24M2P_2MPO_ET_M0

MACRO MUX2_X1_6T_2F_45CPP_24M0P_30M1P_OF0_24M2P_2MPO_ET_M0
  CLASS CORE ;
  ORIGIN 0 0 ;
  FOREIGN MUX2_X1_6T_2F_45CPP_24M0P_30M1P_OF0_24M2P_2MPO_ET_M0 0 0 ;
  SIZE 0.3150 BY 0.1440 ;
  SYMMETRY X Y ;
  SITE coresite ;
  PIN S
    DIRECTION INPUT ;
    USE SIGNAL ;
    PORT
      LAYER M2 ;
        RECT 0.0480 0.1150 0.2820 0.1010 ;
      LAYER M1 ;
        RECT 0.0825 0.1200 0.0975 0.0240 ;
        RECT 0.2025 0.1200 0.2175 0.0240 ;
      LAYER M0 ;
        RECT 0.0125 0.1150 0.1600 0.1010 ;
        RECT 0.1700 0.0430 0.2200 0.0290 ;
    END
  END S
  PIN I0
    DIRECTION INPUT ;
    USE SIGNAL ;
    PORT
      LAYER M0 ;
        RECT 0.0125 0.0670 0.1000 0.0530 ;
    END
  END I0
  PIN I1
    DIRECTION INPUT ;
    USE SIGNAL ;
    PORT
      LAYER M0 ;
        RECT 0.2000 0.0670 0.3025 0.0530 ;
    END
  END I1
  PIN Z
    DIRECTION OUTPUT ;
    USE SIGNAL ;
    PORT
      LAYER M0 ;
        RECT 0.2600 0.0430 0.3025 0.0290 ;
    END
  END Z
  PIN VDD
    DIRECTION INOUT ;
    USE POWER ;
    SHAPE ABUTMENT ;
    PORT
      LAYER M0 ;
        RECT 0.0000 0.1260 0.3150 0.1620 ;
    END
  END VDD
  PIN VSS
    DIRECTION INOUT ;
    USE GROUND ;
    SHAPE ABUTMENT ;
    PORT
      LAYER M0 ;
        RECT 0.0000 -0.0180 0.3150 0.0180 ;
    END
  END VSS
  OBS
      LAYER V0 ;
        RECT 0.1130 0.0290 0.1270 0.0430 ;
        RECT 0.2030 0.0290 0.2170 0.0430 ;
        RECT 0.1130 0.0530 0.1270 0.0670 ;
        RECT 0.1730 0.0530 0.1870 0.0670 ;
        RECT 0.0830 0.1010 0.0970 0.1150 ;
        RECT 0.1730 0.1010 0.1870 0.1150 ;
      LAYER M1 ;
        RECT 0.1125 0.1200 0.1275 0.0240 ;
        RECT 0.1725 0.1200 0.1875 0.0240 ;
      LAYER M0 ;
        RECT 0.1700 0.1010 0.2575 0.1150 ;
        RECT 0.0500 0.0770 0.2800 0.0910 ;
        RECT 0.1100 0.0530 0.1900 0.0670 ;
        RECT 0.0125 0.0290 0.1450 0.0430 ;
      LAYER V1 ;
        RECT 0.2030 0.1010 0.2170 0.1150 ;
        RECT 0.0830 0.1010 0.0970 0.1150 ;
  END
END MUX2_X1_6T_2F_45CPP_24M0P_30M1P_OF0_24M2P_2MPO_ET_M0

MACRO BUF_X1_6T_2F_45CPP_24M0P_30M1P_OF0_24M2P_2MPO_ET_M0
  CLASS CORE ;
  ORIGIN 0 0 ;
  FOREIGN BUF_X1_6T_2F_45CPP_24M0P_30M1P_OF0_24M2P_2MPO_ET_M0 0 0 ;
  SIZE 0.1350 BY 0.1440 ;
  SYMMETRY X Y ;
  SITE coresite ;
  PIN I
    DIRECTION INPUT ;
    USE SIGNAL ;
    PORT
      LAYER M0 ;
        RECT 0.0125 0.1150 0.0550 0.1010 ;
    END
  END I
  PIN Z
    DIRECTION OUTPUT ;
    USE SIGNAL ;
    PORT
      LAYER M0 ;
        RECT 0.0800 0.0430 0.1225 0.0290 ;
    END
  END Z
  PIN VDD
    DIRECTION INOUT ;
    USE POWER ;
    SHAPE ABUTMENT ;
    PORT
      LAYER M0 ;
        RECT 0.0000 0.1260 0.1350 0.1620 ;
    END
  END VDD
  PIN VSS
    DIRECTION INOUT ;
    USE GROUND ;
    SHAPE ABUTMENT ;
    PORT
      LAYER M0 ;
        RECT 0.0000 -0.0180 0.1350 0.0180 ;
    END
  END VSS
  OBS
      LAYER M0 ;
        RECT 0.0125 0.0770 0.1000 0.0910 ;
  END
END BUF_X1_6T_2F_45CPP_24M0P_30M1P_OF0_24M2P_2MPO_ET_M0

MACRO BUF_X2_6T_2F_45CPP_24M0P_30M1P_OF0_24M2P_2MPO_ET_M0
  CLASS CORE ;
  ORIGIN 0 0 ;
  FOREIGN BUF_X2_6T_2F_45CPP_24M0P_30M1P_OF0_24M2P_2MPO_ET_M0 0 0 ;
  SIZE 0.1800 BY 0.1440 ;
  SYMMETRY X Y ;
  SITE coresite ;
  PIN I
    DIRECTION INPUT ;
    USE SIGNAL ;
    PORT
      LAYER M0 ;
        RECT 0.0200 0.1150 0.0700 0.1010 ;
    END
  END I
  PIN Z
    DIRECTION OUTPUT ;
    USE SIGNAL ;
    PORT
      LAYER M0 ;
        RECT 0.0800 0.0430 0.1675 0.0290 ;
    END
  END Z
  PIN VDD
    DIRECTION INOUT ;
    USE POWER ;
    SHAPE ABUTMENT ;
    PORT
      LAYER M0 ;
        RECT 0.0000 0.1260 0.1800 0.1620 ;
    END
  END VDD
  PIN VSS
    DIRECTION INOUT ;
    USE GROUND ;
    SHAPE ABUTMENT ;
    PORT
      LAYER M0 ;
        RECT 0.0000 -0.0180 0.1800 0.0180 ;
    END
  END VSS
  OBS
      LAYER M0 ;
        RECT 0.0125 0.0530 0.1450 0.0670 ;
  END
END BUF_X2_6T_2F_45CPP_24M0P_30M1P_OF0_24M2P_2MPO_ET_M0

MACRO BUF_X4_6T_2F_45CPP_24M0P_30M1P_OF0_24M2P_2MPO_ET_M0
  CLASS CORE ;
  ORIGIN 0 0 ;
  FOREIGN BUF_X4_6T_2F_45CPP_24M0P_30M1P_OF0_24M2P_2MPO_ET_M0 0 0 ;
  SIZE 0.3150 BY 0.1440 ;
  SYMMETRY X Y ;
  SITE coresite ;
  PIN I
    DIRECTION INPUT ;
    USE SIGNAL ;
    PORT
      LAYER M0 ;
        RECT 0.0200 0.1150 0.2575 0.1010 ;
    END
  END I
  PIN Z
    DIRECTION OUTPUT ;
    USE SIGNAL ;
    PORT
      LAYER M0 ;
        RECT 0.1250 0.0430 0.2575 0.0290 ;
    END
  END Z
  PIN VDD
    DIRECTION INOUT ;
    USE POWER ;
    SHAPE ABUTMENT ;
    PORT
      LAYER M0 ;
        RECT 0.0000 0.1260 0.3150 0.1620 ;
    END
  END VDD
  PIN VSS
    DIRECTION INOUT ;
    USE GROUND ;
    SHAPE ABUTMENT ;
    PORT
      LAYER M0 ;
        RECT 0.0000 -0.0180 0.3150 0.0180 ;
    END
  END VSS
  OBS
      LAYER M0 ;
        RECT 0.0575 0.0770 0.2800 0.0910 ;
  END
END BUF_X4_6T_2F_45CPP_24M0P_30M1P_OF0_24M2P_2MPO_ET_M0

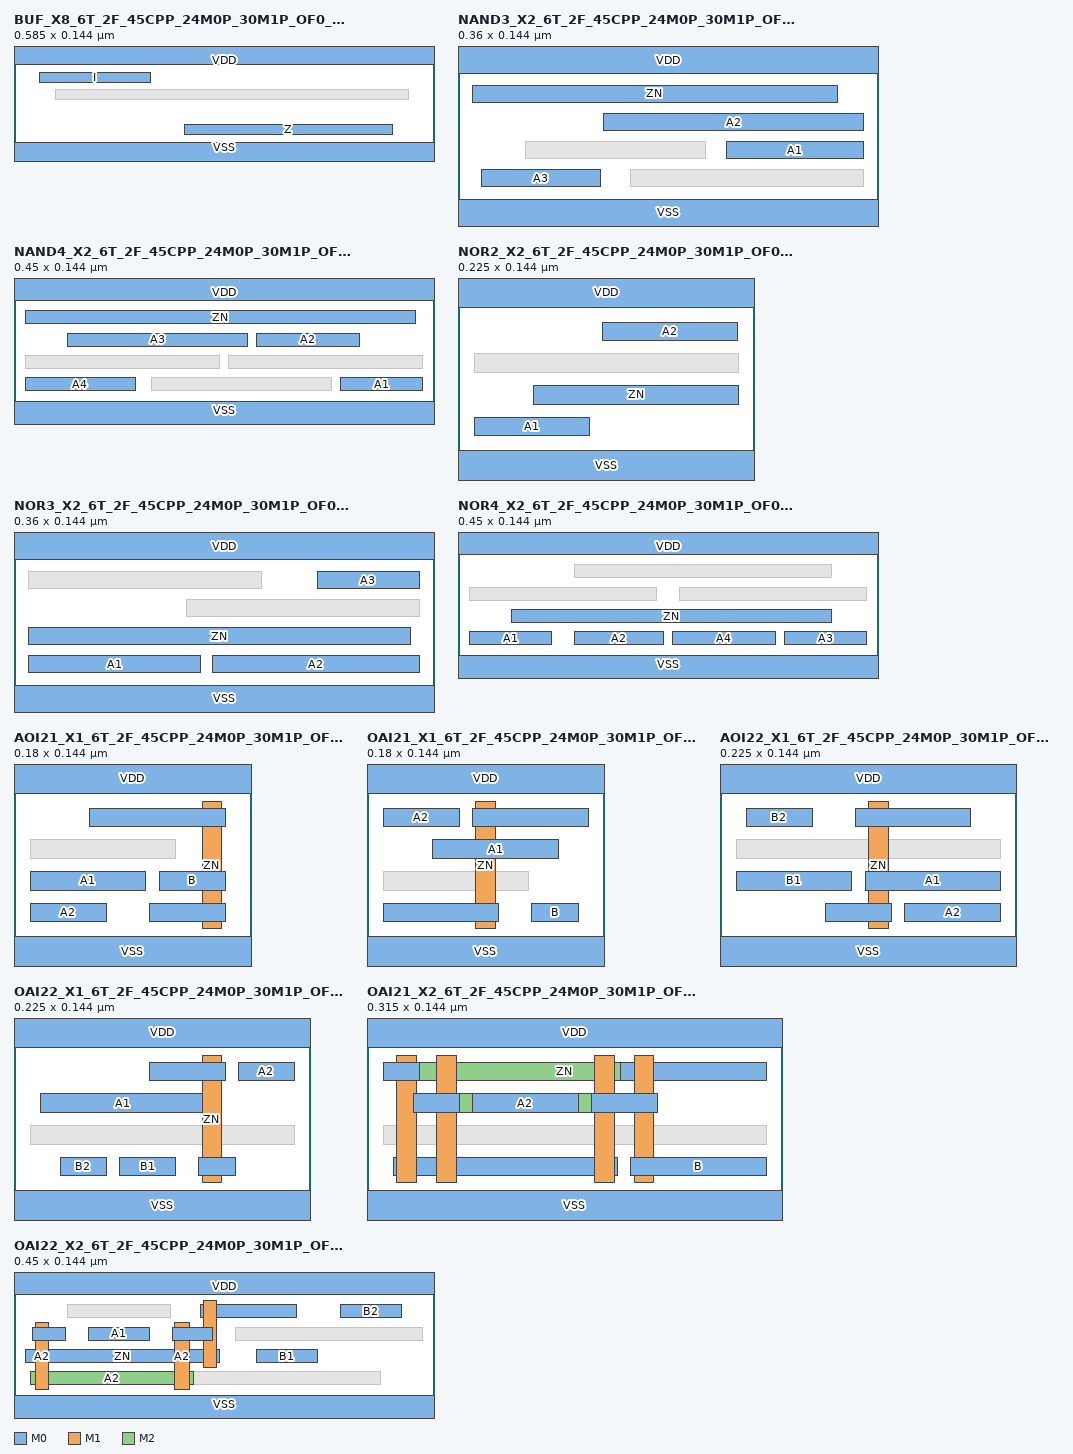
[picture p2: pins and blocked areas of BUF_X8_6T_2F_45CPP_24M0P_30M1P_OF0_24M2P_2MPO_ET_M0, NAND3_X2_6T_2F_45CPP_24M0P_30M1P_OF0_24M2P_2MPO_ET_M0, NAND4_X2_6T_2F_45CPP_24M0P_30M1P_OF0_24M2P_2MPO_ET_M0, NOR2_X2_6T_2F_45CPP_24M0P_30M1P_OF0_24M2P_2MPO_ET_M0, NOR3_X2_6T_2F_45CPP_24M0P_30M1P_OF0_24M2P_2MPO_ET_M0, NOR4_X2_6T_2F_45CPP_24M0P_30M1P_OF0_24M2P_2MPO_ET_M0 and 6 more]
MACRO BUF_X8_6T_2F_45CPP_24M0P_30M1P_OF0_24M2P_2MPO_ET_M0
  CLASS CORE ;
  ORIGIN 0 0 ;
  FOREIGN BUF_X8_6T_2F_45CPP_24M0P_30M1P_OF0_24M2P_2MPO_ET_M0 0 0 ;
  SIZE 0.5850 BY 0.1440 ;
  SYMMETRY X Y ;
  SITE coresite ;
  PIN I
    DIRECTION INPUT ;
    USE SIGNAL ;
    PORT
      LAYER M0 ;
        RECT 0.0350 0.1150 0.1900 0.1010 ;
    END
  END I
  PIN Z
    DIRECTION OUTPUT ;
    USE SIGNAL ;
    PORT
      LAYER M0 ;
        RECT 0.2375 0.0430 0.5275 0.0290 ;
    END
  END Z
  PIN VDD
    DIRECTION INOUT ;
    USE POWER ;
    SHAPE ABUTMENT ;
    PORT
      LAYER M0 ;
        RECT 0.0000 0.1260 0.5850 0.1620 ;
    END
  END VDD
  PIN VSS
    DIRECTION INOUT ;
    USE GROUND ;
    SHAPE ABUTMENT ;
    PORT
      LAYER M0 ;
        RECT 0.0000 -0.0180 0.5850 0.0180 ;
    END
  END VSS
  OBS
      LAYER M0 ;
        RECT 0.0575 0.0770 0.5500 0.0910 ;
  END
END BUF_X8_6T_2F_45CPP_24M0P_30M1P_OF0_24M2P_2MPO_ET_M0

MACRO NAND3_X2_6T_2F_45CPP_24M0P_30M1P_OF0_24M2P_2MPO_ET_M0
  CLASS CORE ;
  ORIGIN 0 0 ;
  FOREIGN NAND3_X2_6T_2F_45CPP_24M0P_30M1P_OF0_24M2P_2MPO_ET_M0 0 0 ;
  SIZE 0.3600 BY 0.1440 ;
  SYMMETRY X Y ;
  SITE coresite ;
  PIN ZN
    DIRECTION OUTPUT ;
    USE SIGNAL ;
    PORT
      LAYER M0 ;
        RECT 0.0125 0.1150 0.3250 0.1010 ;
    END
  END ZN
  PIN A2
    DIRECTION INPUT ;
    USE SIGNAL ;
    PORT
      LAYER M0 ;
        RECT 0.1250 0.0910 0.3475 0.0770 ;
    END
  END A2
  PIN A1
    DIRECTION INPUT ;
    USE SIGNAL ;
    PORT
      LAYER M0 ;
        RECT 0.2300 0.0670 0.3475 0.0530 ;
    END
  END A1
  PIN A3
    DIRECTION INPUT ;
    USE SIGNAL ;
    PORT
      LAYER M0 ;
        RECT 0.0200 0.0430 0.1225 0.0290 ;
    END
  END A3
  PIN VDD
    DIRECTION INOUT ;
    USE POWER ;
    SHAPE ABUTMENT ;
    PORT
      LAYER M0 ;
        RECT 0.0000 0.1260 0.3600 0.1620 ;
    END
  END VDD
  PIN VSS
    DIRECTION INOUT ;
    USE GROUND ;
    SHAPE ABUTMENT ;
    PORT
      LAYER M0 ;
        RECT 0.0000 -0.0180 0.3600 0.0180 ;
    END
  END VSS
  OBS
      LAYER M0 ;
        RECT 0.0575 0.0530 0.2125 0.0670 ;
        RECT 0.1475 0.0290 0.3475 0.0430 ;
  END
END NAND3_X2_6T_2F_45CPP_24M0P_30M1P_OF0_24M2P_2MPO_ET_M0

MACRO NAND4_X2_6T_2F_45CPP_24M0P_30M1P_OF0_24M2P_2MPO_ET_M0
  CLASS CORE ;
  ORIGIN 0 0 ;
  FOREIGN NAND4_X2_6T_2F_45CPP_24M0P_30M1P_OF0_24M2P_2MPO_ET_M0 0 0 ;
  SIZE 0.4500 BY 0.1440 ;
  SYMMETRY X Y ;
  SITE coresite ;
  PIN ZN
    DIRECTION OUTPUT ;
    USE SIGNAL ;
    PORT
      LAYER M0 ;
        RECT 0.0125 0.1150 0.4300 0.1010 ;
    END
  END ZN
  PIN A3
    DIRECTION INPUT ;
    USE SIGNAL ;
    PORT
      LAYER M0 ;
        RECT 0.0575 0.0910 0.2500 0.0770 ;
    END
  END A3
  PIN A2
    DIRECTION INPUT ;
    USE SIGNAL ;
    PORT
      LAYER M0 ;
        RECT 0.2600 0.0910 0.3700 0.0770 ;
    END
  END A2
  PIN A4
    DIRECTION INPUT ;
    USE SIGNAL ;
    PORT
      LAYER M0 ;
        RECT 0.0125 0.0430 0.1300 0.0290 ;
    END
  END A4
  PIN A1
    DIRECTION INPUT ;
    USE SIGNAL ;
    PORT
      LAYER M0 ;
        RECT 0.3500 0.0430 0.4375 0.0290 ;
    END
  END A1
  PIN VDD
    DIRECTION INOUT ;
    USE POWER ;
    SHAPE ABUTMENT ;
    PORT
      LAYER M0 ;
        RECT 0.0000 0.1260 0.4500 0.1620 ;
    END
  END VDD
  PIN VSS
    DIRECTION INOUT ;
    USE GROUND ;
    SHAPE ABUTMENT ;
    PORT
      LAYER M0 ;
        RECT 0.0000 -0.0180 0.4500 0.0180 ;
    END
  END VSS
  OBS
      LAYER M0 ;
        RECT 0.0125 0.0530 0.2200 0.0670 ;
        RECT 0.2300 0.0530 0.4375 0.0670 ;
        RECT 0.1475 0.0290 0.3400 0.0430 ;
  END
END NAND4_X2_6T_2F_45CPP_24M0P_30M1P_OF0_24M2P_2MPO_ET_M0

MACRO NOR2_X2_6T_2F_45CPP_24M0P_30M1P_OF0_24M2P_2MPO_ET_M0
  CLASS CORE ;
  ORIGIN 0 0 ;
  FOREIGN NOR2_X2_6T_2F_45CPP_24M0P_30M1P_OF0_24M2P_2MPO_ET_M0 0 0 ;
  SIZE 0.2250 BY 0.1440 ;
  SYMMETRY X Y ;
  SITE coresite ;
  PIN ZN
    DIRECTION OUTPUT ;
    USE SIGNAL ;
    PORT
      LAYER M0 ;
        RECT 0.0575 0.0670 0.2125 0.0530 ;
    END
  END ZN
  PIN A1
    DIRECTION INPUT ;
    USE SIGNAL ;
    PORT
      LAYER M0 ;
        RECT 0.0125 0.0430 0.1000 0.0290 ;
    END
  END A1
  PIN A2
    DIRECTION INPUT ;
    USE SIGNAL ;
    PORT
      LAYER M0 ;
        RECT 0.1095 0.1150 0.2120 0.1010 ;
    END
  END A2
  PIN VDD
    DIRECTION INOUT ;
    USE POWER ;
    SHAPE ABUTMENT ;
    PORT
      LAYER M0 ;
        RECT 0.0000 0.1260 0.2250 0.1620 ;
    END
  END VDD
  PIN VSS
    DIRECTION INOUT ;
    USE GROUND ;
    SHAPE ABUTMENT ;
    PORT
      LAYER M0 ;
        RECT 0.0000 -0.0180 0.2250 0.0180 ;
    END
  END VSS
  OBS
      LAYER M0 ;
        RECT 0.0125 0.0770 0.2125 0.0910 ;
  END
END NOR2_X2_6T_2F_45CPP_24M0P_30M1P_OF0_24M2P_2MPO_ET_M0

MACRO NOR3_X2_6T_2F_45CPP_24M0P_30M1P_OF0_24M2P_2MPO_ET_M0
  CLASS CORE ;
  ORIGIN 0 0 ;
  FOREIGN NOR3_X2_6T_2F_45CPP_24M0P_30M1P_OF0_24M2P_2MPO_ET_M0 0 0 ;
  SIZE 0.3600 BY 0.1440 ;
  SYMMETRY X Y ;
  SITE coresite ;
  PIN A3
    DIRECTION INPUT ;
    USE SIGNAL ;
    PORT
      LAYER M0 ;
        RECT 0.2600 0.1150 0.3475 0.1010 ;
    END
  END A3
  PIN ZN
    DIRECTION OUTPUT ;
    USE SIGNAL ;
    PORT
      LAYER M0 ;
        RECT 0.0125 0.0670 0.3400 0.0530 ;
    END
  END ZN
  PIN A1
    DIRECTION INPUT ;
    USE SIGNAL ;
    PORT
      LAYER M0 ;
        RECT 0.0125 0.0430 0.1600 0.0290 ;
    END
  END A1
  PIN A2
    DIRECTION INPUT ;
    USE SIGNAL ;
    PORT
      LAYER M0 ;
        RECT 0.1700 0.0430 0.3475 0.0290 ;
    END
  END A2
  PIN VDD
    DIRECTION INOUT ;
    USE POWER ;
    SHAPE ABUTMENT ;
    PORT
      LAYER M0 ;
        RECT 0.0000 0.1260 0.3600 0.1620 ;
    END
  END VDD
  PIN VSS
    DIRECTION INOUT ;
    USE GROUND ;
    SHAPE ABUTMENT ;
    PORT
      LAYER M0 ;
        RECT 0.0000 -0.0180 0.3600 0.0180 ;
    END
  END VSS
  OBS
      LAYER M0 ;
        RECT 0.0125 0.1010 0.2125 0.1150 ;
        RECT 0.1475 0.0770 0.3475 0.0910 ;
  END
END NOR3_X2_6T_2F_45CPP_24M0P_30M1P_OF0_24M2P_2MPO_ET_M0

MACRO NOR4_X2_6T_2F_45CPP_24M0P_30M1P_OF0_24M2P_2MPO_ET_M0
  CLASS CORE ;
  ORIGIN 0 0 ;
  FOREIGN NOR4_X2_6T_2F_45CPP_24M0P_30M1P_OF0_24M2P_2MPO_ET_M0 0 0 ;
  SIZE 0.4500 BY 0.1440 ;
  SYMMETRY X Y ;
  SITE coresite ;
  PIN ZN
    DIRECTION OUTPUT ;
    USE SIGNAL ;
    PORT
      LAYER M0 ;
        RECT 0.0575 0.0670 0.4000 0.0530 ;
    END
  END ZN
  PIN A1
    DIRECTION INPUT ;
    USE SIGNAL ;
    PORT
      LAYER M0 ;
        RECT 0.0125 0.0430 0.1000 0.0290 ;
    END
  END A1
  PIN A2
    DIRECTION INPUT ;
    USE SIGNAL ;
    PORT
      LAYER M0 ;
        RECT 0.1250 0.0430 0.2200 0.0290 ;
    END
  END A2
  PIN A4
    DIRECTION INPUT ;
    USE SIGNAL ;
    PORT
      LAYER M0 ;
        RECT 0.2300 0.0430 0.3400 0.0290 ;
    END
  END A4
  PIN A3
    DIRECTION INPUT ;
    USE SIGNAL ;
    PORT
      LAYER M0 ;
        RECT 0.3500 0.0430 0.4375 0.0290 ;
    END
  END A3
  PIN VDD
    DIRECTION INOUT ;
    USE POWER ;
    SHAPE ABUTMENT ;
    PORT
      LAYER M0 ;
        RECT 0.0000 0.1260 0.4500 0.1620 ;
    END
  END VDD
  PIN VSS
    DIRECTION INOUT ;
    USE GROUND ;
    SHAPE ABUTMENT ;
    PORT
      LAYER M0 ;
        RECT 0.0000 -0.0180 0.4500 0.0180 ;
    END
  END VSS
  OBS
      LAYER M0 ;
        RECT 0.1250 0.1010 0.4000 0.1150 ;
        RECT 0.0125 0.0770 0.2125 0.0910 ;
        RECT 0.2375 0.0770 0.4375 0.0910 ;
  END
END NOR4_X2_6T_2F_45CPP_24M0P_30M1P_OF0_24M2P_2MPO_ET_M0

MACRO AOI21_X1_6T_2F_45CPP_24M0P_30M1P_OF0_24M2P_2MPO_ET_M0
  CLASS CORE ;
  ORIGIN 0 0 ;
  FOREIGN AOI21_X1_6T_2F_45CPP_24M0P_30M1P_OF0_24M2P_2MPO_ET_M0 0 0 ;
  SIZE 0.1800 BY 0.1440 ;
  SYMMETRY X Y ;
  SITE coresite ;
  PIN ZN
    DIRECTION OUTPUT ;
    USE SIGNAL ;
    PORT
      LAYER M1 ;
        RECT 0.1425 0.1200 0.1575 0.0240 ;
      LAYER M0 ;
        RECT 0.0575 0.1150 0.1600 0.1010 ;
        RECT 0.1025 0.0430 0.1600 0.0290 ;
    END
  END ZN
  PIN A1
    DIRECTION INPUT ;
    USE SIGNAL ;
    PORT
      LAYER M0 ;
        RECT 0.0125 0.0670 0.1000 0.0530 ;
    END
  END A1
  PIN B
    DIRECTION INPUT ;
    USE SIGNAL ;
    PORT
      LAYER M0 ;
        RECT 0.1100 0.0670 0.1600 0.0530 ;
    END
  END B
  PIN A2
    DIRECTION INPUT ;
    USE SIGNAL ;
    PORT
      LAYER M0 ;
        RECT 0.0125 0.0430 0.0700 0.0290 ;
    END
  END A2
  PIN VDD
    DIRECTION INOUT ;
    USE POWER ;
    SHAPE ABUTMENT ;
    PORT
      LAYER M0 ;
        RECT 0.0000 0.1260 0.1800 0.1620 ;
    END
  END VDD
  PIN VSS
    DIRECTION INOUT ;
    USE GROUND ;
    SHAPE ABUTMENT ;
    PORT
      LAYER M0 ;
        RECT 0.0000 -0.0180 0.1800 0.0180 ;
    END
  END VSS
  OBS
      LAYER V0 ;
        RECT 0.1430 0.0290 0.1570 0.0430 ;
        RECT 0.1430 0.1010 0.1570 0.1150 ;
      LAYER M0 ;
        RECT 0.0125 0.0770 0.1225 0.0910 ;
  END
END AOI21_X1_6T_2F_45CPP_24M0P_30M1P_OF0_24M2P_2MPO_ET_M0

MACRO OAI21_X1_6T_2F_45CPP_24M0P_30M1P_OF0_24M2P_2MPO_ET_M0
  CLASS CORE ;
  ORIGIN 0 0 ;
  FOREIGN OAI21_X1_6T_2F_45CPP_24M0P_30M1P_OF0_24M2P_2MPO_ET_M0 0 0 ;
  SIZE 0.1800 BY 0.1440 ;
  SYMMETRY X Y ;
  SITE coresite ;
  PIN ZN
    DIRECTION OUTPUT ;
    USE SIGNAL ;
    PORT
      LAYER M1 ;
        RECT 0.0825 0.1200 0.0975 0.0240 ;
      LAYER M0 ;
        RECT 0.0800 0.1150 0.1675 0.1010 ;
        RECT 0.0125 0.0430 0.1000 0.0290 ;
    END
  END ZN
  PIN A2
    DIRECTION INPUT ;
    USE SIGNAL ;
    PORT
      LAYER M0 ;
        RECT 0.0125 0.1150 0.0700 0.1010 ;
    END
  END A2
  PIN A1
    DIRECTION INPUT ;
    USE SIGNAL ;
    PORT
      LAYER M0 ;
        RECT 0.0500 0.0910 0.1450 0.0770 ;
    END
  END A1
  PIN B
    DIRECTION INPUT ;
    USE SIGNAL ;
    PORT
      LAYER M0 ;
        RECT 0.1250 0.0430 0.1600 0.0290 ;
    END
  END B
  PIN VDD
    DIRECTION INOUT ;
    USE POWER ;
    SHAPE ABUTMENT ;
    PORT
      LAYER M0 ;
        RECT 0.0000 0.1260 0.1800 0.1620 ;
    END
  END VDD
  PIN VSS
    DIRECTION INOUT ;
    USE GROUND ;
    SHAPE ABUTMENT ;
    PORT
      LAYER M0 ;
        RECT 0.0000 -0.0180 0.1800 0.0180 ;
    END
  END VSS
  OBS
      LAYER V0 ;
        RECT 0.0830 0.0290 0.0970 0.0430 ;
        RECT 0.0830 0.1010 0.0970 0.1150 ;
      LAYER M0 ;
        RECT 0.0125 0.0530 0.1225 0.0670 ;
  END
END OAI21_X1_6T_2F_45CPP_24M0P_30M1P_OF0_24M2P_2MPO_ET_M0

MACRO AOI22_X1_6T_2F_45CPP_24M0P_30M1P_OF0_24M2P_2MPO_ET_M0
  CLASS CORE ;
  ORIGIN 0 0 ;
  FOREIGN AOI22_X1_6T_2F_45CPP_24M0P_30M1P_OF0_24M2P_2MPO_ET_M0 0 0 ;
  SIZE 0.2250 BY 0.1440 ;
  SYMMETRY X Y ;
  SITE coresite ;
  PIN ZN
    DIRECTION OUTPUT ;
    USE SIGNAL ;
    PORT
      LAYER M1 ;
        RECT 0.1125 0.1200 0.1275 0.0240 ;
      LAYER M0 ;
        RECT 0.1025 0.1150 0.1900 0.1010 ;
        RECT 0.0800 0.0430 0.1300 0.0290 ;
    END
  END ZN
  PIN B1
    DIRECTION INPUT ;
    USE SIGNAL ;
    PORT
      LAYER M0 ;
        RECT 0.0125 0.0670 0.1000 0.0530 ;
    END
  END B1
  PIN A1
    DIRECTION INPUT ;
    USE SIGNAL ;
    PORT
      LAYER M0 ;
        RECT 0.1100 0.0670 0.2125 0.0530 ;
    END
  END A1
  PIN B2
    DIRECTION INPUT ;
    USE SIGNAL ;
    PORT
      LAYER M0 ;
        RECT 0.0200 0.1150 0.0700 0.1010 ;
    END
  END B2
  PIN A2
    DIRECTION INPUT ;
    USE SIGNAL ;
    PORT
      LAYER M0 ;
        RECT 0.1400 0.0430 0.2125 0.0290 ;
    END
  END A2
  PIN VDD
    DIRECTION INOUT ;
    USE POWER ;
    SHAPE ABUTMENT ;
    PORT
      LAYER M0 ;
        RECT 0.0000 0.1260 0.2250 0.1620 ;
    END
  END VDD
  PIN VSS
    DIRECTION INOUT ;
    USE GROUND ;
    SHAPE ABUTMENT ;
    PORT
      LAYER M0 ;
        RECT 0.0000 -0.0180 0.2250 0.0180 ;
    END
  END VSS
  OBS
      LAYER V0 ;
        RECT 0.1130 0.0290 0.1270 0.0430 ;
        RECT 0.1130 0.1010 0.1270 0.1150 ;
      LAYER M0 ;
        RECT 0.0125 0.0770 0.2125 0.0910 ;
  END
END AOI22_X1_6T_2F_45CPP_24M0P_30M1P_OF0_24M2P_2MPO_ET_M0

MACRO OAI22_X1_6T_2F_45CPP_24M0P_30M1P_OF0_24M2P_2MPO_ET_M0
  CLASS CORE ;
  ORIGIN 0 0 ;
  FOREIGN OAI22_X1_6T_2F_45CPP_24M0P_30M1P_OF0_24M2P_2MPO_ET_M0 0 0 ;
  SIZE 0.2250 BY 0.1440 ;
  SYMMETRY X Y ;
  SITE coresite ;
  PIN ZN
    DIRECTION OUTPUT ;
    USE SIGNAL ;
    PORT
      LAYER M1 ;
        RECT 0.1425 0.1200 0.1575 0.0240 ;
      LAYER M0 ;
        RECT 0.1025 0.1150 0.1600 0.1010 ;
        RECT 0.1400 0.0430 0.1675 0.0290 ;
    END
  END ZN
  PIN A2
    DIRECTION INPUT ;
    USE SIGNAL ;
    PORT
      LAYER M0 ;
        RECT 0.1700 0.1150 0.2125 0.1010 ;
    END
  END A2
  PIN A1
    DIRECTION INPUT ;
    USE SIGNAL ;
    PORT
      LAYER M0 ;
        RECT 0.0200 0.0910 0.1450 0.0770 ;
    END
  END A1
  PIN B2
    DIRECTION INPUT ;
    USE SIGNAL ;
    PORT
      LAYER M0 ;
        RECT 0.0350 0.0430 0.0700 0.0290 ;
    END
  END B2
  PIN B1
    DIRECTION INPUT ;
    USE SIGNAL ;
    PORT
      LAYER M0 ;
        RECT 0.0800 0.0430 0.1225 0.0290 ;
    END
  END B1
  PIN VDD
    DIRECTION INOUT ;
    USE POWER ;
    SHAPE ABUTMENT ;
    PORT
      LAYER M0 ;
        RECT 0.0000 0.1260 0.2250 0.1620 ;
    END
  END VDD
  PIN VSS
    DIRECTION INOUT ;
    USE GROUND ;
    SHAPE ABUTMENT ;
    PORT
      LAYER M0 ;
        RECT 0.0000 -0.0180 0.2250 0.0180 ;
    END
  END VSS
  OBS
      LAYER V0 ;
        RECT 0.1430 0.0290 0.1570 0.0430 ;
        RECT 0.1430 0.1010 0.1570 0.1150 ;
      LAYER M0 ;
        RECT 0.0125 0.0530 0.2125 0.0670 ;
  END
END OAI22_X1_6T_2F_45CPP_24M0P_30M1P_OF0_24M2P_2MPO_ET_M0

MACRO OAI21_X2_6T_2F_45CPP_24M0P_30M1P_OF0_24M2P_2MPO_ET_M0
  CLASS CORE ;
  ORIGIN 0 0 ;
  FOREIGN OAI21_X2_6T_2F_45CPP_24M0P_30M1P_OF0_24M2P_2MPO_ET_M0 0 0 ;
  SIZE 0.3150 BY 0.1440 ;
  SYMMETRY X Y ;
  SITE coresite ;
  PIN ZN
    DIRECTION OUTPUT ;
    USE SIGNAL ;
    PORT
      LAYER M2 ;
        RECT 0.0180 0.1150 0.2820 0.1010 ;
      LAYER M1 ;
        RECT 0.0225 0.1200 0.0375 0.0240 ;
        RECT 0.2025 0.1200 0.2175 0.0240 ;
      LAYER M0 ;
        RECT 0.0125 0.1150 0.0400 0.1010 ;
        RECT 0.0200 0.0430 0.1900 0.0290 ;
        RECT 0.1925 0.1150 0.3025 0.1010 ;
    END
  END ZN
  PIN A1
    DIRECTION INPUT ;
    USE SIGNAL ;
    PORT
      LAYER M2 ;
        RECT 0.0480 0.0910 0.1920 0.0770 ;
      LAYER M1 ;
        RECT 0.0525 0.1200 0.0675 0.0240 ;
        RECT 0.1725 0.1200 0.1875 0.0240 ;
      LAYER M0 ;
        RECT 0.0350 0.0910 0.0700 0.0770 ;
        RECT 0.1700 0.0910 0.2200 0.0770 ;
    END
  END A1
  PIN A2
    DIRECTION INPUT ;
    USE SIGNAL ;
    PORT
      LAYER M0 ;
        RECT 0.0800 0.0910 0.1600 0.0770 ;
    END
  END A2
  PIN B
    DIRECTION INPUT ;
    USE SIGNAL ;
    PORT
      LAYER M0 ;
        RECT 0.2000 0.0430 0.3025 0.0290 ;
    END
  END B
  PIN VDD
    DIRECTION INOUT ;
    USE POWER ;
    SHAPE ABUTMENT ;
    PORT
      LAYER M0 ;
        RECT 0.0000 0.1260 0.3150 0.1620 ;
    END
  END VDD
  PIN VSS
    DIRECTION INOUT ;
    USE GROUND ;
    SHAPE ABUTMENT ;
    PORT
      LAYER M0 ;
        RECT 0.0000 -0.0180 0.3150 0.0180 ;
    END
  END VSS
  OBS
      LAYER V0 ;
        RECT 0.0230 0.0290 0.0370 0.0430 ;
        RECT 0.0530 0.0770 0.0670 0.0910 ;
        RECT 0.1730 0.0770 0.1870 0.0910 ;
        RECT 0.0230 0.1010 0.0370 0.1150 ;
        RECT 0.2030 0.1010 0.2170 0.1150 ;
      LAYER M0 ;
        RECT 0.0575 0.1010 0.1675 0.1150 ;
        RECT 0.0125 0.0530 0.3025 0.0670 ;
      LAYER V1 ;
        RECT 0.1730 0.0770 0.1870 0.0910 ;
        RECT 0.0530 0.0770 0.0670 0.0910 ;
        RECT 0.2030 0.1010 0.2170 0.1150 ;
        RECT 0.0230 0.1010 0.0370 0.1150 ;
  END
END OAI21_X2_6T_2F_45CPP_24M0P_30M1P_OF0_24M2P_2MPO_ET_M0

MACRO OAI22_X2_6T_2F_45CPP_24M0P_30M1P_OF0_24M2P_2MPO_ET_M0
  CLASS CORE ;
  ORIGIN 0 0 ;
  FOREIGN OAI22_X2_6T_2F_45CPP_24M0P_30M1P_OF0_24M2P_2MPO_ET_M0 0 0 ;
  SIZE 0.4500 BY 0.1440 ;
  SYMMETRY X Y ;
  SITE coresite ;
  PIN A2
    DIRECTION INPUT ;
    USE SIGNAL ;
    PORT
      LAYER M1 ;
        RECT 0.0225 0.0960 0.0375 0.0240 ;
      LAYER M0 ;
        RECT 0.0200 0.0910 0.0550 0.0770 ;
    END
  END A2
  PIN A2
    DIRECTION INPUT ;
    USE SIGNAL ;
    PORT
      LAYER M1 ;
        RECT 0.1725 0.0960 0.1875 0.0240 ;
      LAYER M0 ;
        RECT 0.1700 0.0910 0.2125 0.0770 ;
    END
  END A2
  PIN ZN
    DIRECTION OUTPUT ;
    USE SIGNAL ;
    PORT
      LAYER M1 ;
        RECT 0.2025 0.1200 0.2175 0.0480 ;
      LAYER M0 ;
        RECT 0.0125 0.0670 0.2200 0.0530 ;
        RECT 0.2000 0.1150 0.3025 0.1010 ;
    END
  END ZN
  PIN A2
    DIRECTION INPUT ;
    USE SIGNAL ;
    PORT
      LAYER M2 ;
        RECT 0.0180 0.0430 0.1920 0.0290 ;
    END
  END A2
  PIN B1
    DIRECTION INPUT ;
    USE SIGNAL ;
    PORT
      LAYER M0 ;
        RECT 0.2600 0.0670 0.3250 0.0530 ;
    END
  END B1
  PIN A1
    DIRECTION INPUT ;
    USE SIGNAL ;
    PORT
      LAYER M0 ;
        RECT 0.0800 0.0910 0.1450 0.0770 ;
    END
  END A1
  PIN B2
    DIRECTION INPUT ;
    USE SIGNAL ;
    PORT
      LAYER M0 ;
        RECT 0.3500 0.1150 0.4150 0.1010 ;
    END
  END B2
  PIN VDD
    DIRECTION INOUT ;
    USE POWER ;
    SHAPE ABUTMENT ;
    PORT
      LAYER M0 ;
        RECT 0.0000 0.1260 0.4500 0.1620 ;
    END
  END VDD
  PIN VSS
    DIRECTION INOUT ;
    USE GROUND ;
    SHAPE ABUTMENT ;
    PORT
      LAYER M0 ;
        RECT 0.0000 -0.0180 0.4500 0.0180 ;
    END
  END VSS
  OBS
      LAYER V1 ;
        RECT 0.0230 0.0290 0.0370 0.0430 ;
        RECT 0.1730 0.0290 0.1870 0.0430 ;
      LAYER V0 ;
        RECT 0.2030 0.0530 0.2170 0.0670 ;
        RECT 0.0230 0.0770 0.0370 0.0910 ;
        RECT 0.1730 0.0770 0.1870 0.0910 ;
        RECT 0.2030 0.1010 0.2170 0.1150 ;
      LAYER M0 ;
        RECT 0.0575 0.0290 0.3925 0.0430 ;
        RECT 0.2375 0.0770 0.4375 0.0910 ;
        RECT 0.0575 0.1010 0.1675 0.1150 ;
  END
END OAI22_X2_6T_2F_45CPP_24M0P_30M1P_OF0_24M2P_2MPO_ET_M0

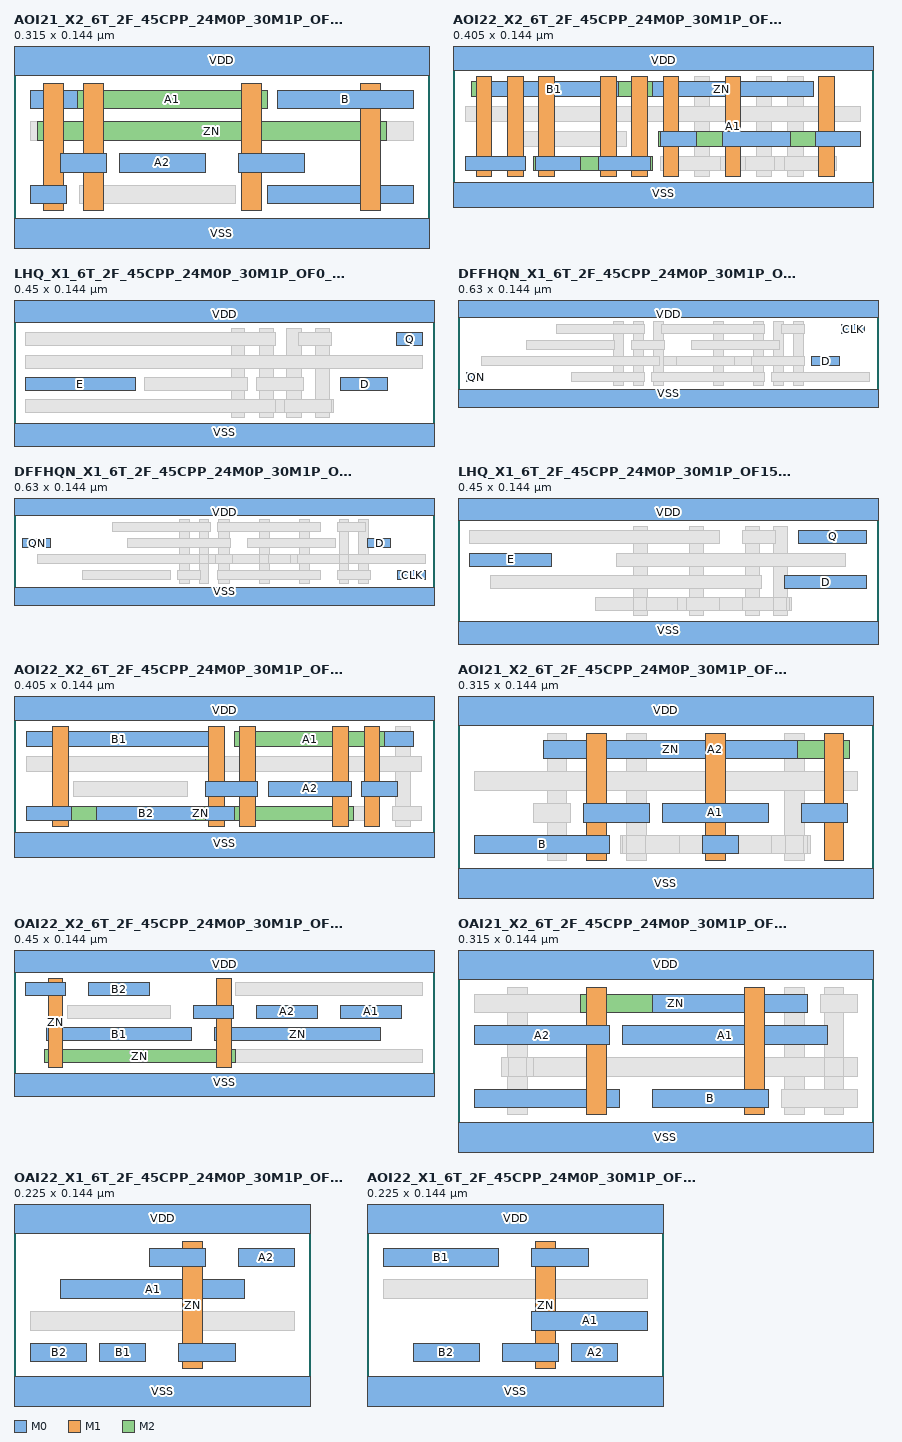
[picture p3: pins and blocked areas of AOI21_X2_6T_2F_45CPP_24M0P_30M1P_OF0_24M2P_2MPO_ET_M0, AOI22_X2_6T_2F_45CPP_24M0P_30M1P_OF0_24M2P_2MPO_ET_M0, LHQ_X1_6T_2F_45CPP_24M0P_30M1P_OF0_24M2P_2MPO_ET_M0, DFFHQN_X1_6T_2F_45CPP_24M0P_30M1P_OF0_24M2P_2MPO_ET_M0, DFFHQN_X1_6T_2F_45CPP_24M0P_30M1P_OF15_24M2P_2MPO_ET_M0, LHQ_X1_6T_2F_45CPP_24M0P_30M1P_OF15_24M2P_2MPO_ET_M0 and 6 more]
MACRO AOI21_X2_6T_2F_45CPP_24M0P_30M1P_OF0_24M2P_2MPO_ET_M0
  CLASS CORE ;
  ORIGIN 0 0 ;
  FOREIGN AOI21_X2_6T_2F_45CPP_24M0P_30M1P_OF0_24M2P_2MPO_ET_M0 0 0 ;
  SIZE 0.3150 BY 0.1440 ;
  SYMMETRY X Y ;
  SITE coresite ;
  PIN A1
    DIRECTION INPUT ;
    USE SIGNAL ;
    PORT
      LAYER M2 ;
        RECT 0.0480 0.1150 0.1920 0.1010 ;
      LAYER M1 ;
        RECT 0.0525 0.1200 0.0675 0.0240 ;
        RECT 0.1725 0.1200 0.1875 0.0240 ;
      LAYER M0 ;
        RECT 0.0350 0.0670 0.0700 0.0530 ;
        RECT 0.1700 0.0670 0.2200 0.0530 ;
    END
  END A1
  PIN ZN
    DIRECTION OUTPUT ;
    USE SIGNAL ;
    PORT
      LAYER M2 ;
        RECT 0.0180 0.0910 0.2820 0.0770 ;
      LAYER M1 ;
        RECT 0.0225 0.1200 0.0375 0.0240 ;
        RECT 0.2625 0.1200 0.2775 0.0240 ;
      LAYER M0 ;
        RECT 0.0125 0.1150 0.1675 0.1010 ;
        RECT 0.0125 0.0430 0.0400 0.0290 ;
        RECT 0.1925 0.0430 0.3025 0.0290 ;
    END
  END ZN
  PIN B
    DIRECTION INPUT ;
    USE SIGNAL ;
    PORT
      LAYER M0 ;
        RECT 0.2000 0.1150 0.3025 0.1010 ;
    END
  END B
  PIN A2
    DIRECTION INPUT ;
    USE SIGNAL ;
    PORT
      LAYER M0 ;
        RECT 0.0800 0.0670 0.1450 0.0530 ;
    END
  END A2
  PIN VDD
    DIRECTION INOUT ;
    USE POWER ;
    SHAPE ABUTMENT ;
    PORT
      LAYER M0 ;
        RECT 0.0000 0.1260 0.3150 0.1620 ;
    END
  END VDD
  PIN VSS
    DIRECTION INOUT ;
    USE GROUND ;
    SHAPE ABUTMENT ;
    PORT
      LAYER M0 ;
        RECT 0.0000 -0.0180 0.3150 0.0180 ;
    END
  END VSS
  OBS
      LAYER V0 ;
        RECT 0.0230 0.0290 0.0370 0.0430 ;
        RECT 0.2630 0.0290 0.2770 0.0430 ;
        RECT 0.0530 0.0530 0.0670 0.0670 ;
        RECT 0.1730 0.0530 0.1870 0.0670 ;
        RECT 0.0230 0.1010 0.0370 0.1150 ;
      LAYER M0 ;
        RECT 0.0125 0.0770 0.3025 0.0910 ;
        RECT 0.0500 0.0290 0.1675 0.0430 ;
      LAYER V1 ;
        RECT 0.2630 0.0770 0.2770 0.0910 ;
        RECT 0.0230 0.0770 0.0370 0.0910 ;
        RECT 0.1730 0.1010 0.1870 0.1150 ;
        RECT 0.0530 0.1010 0.0670 0.1150 ;
  END
END AOI21_X2_6T_2F_45CPP_24M0P_30M1P_OF0_24M2P_2MPO_ET_M0

MACRO AOI22_X2_6T_2F_45CPP_24M0P_30M1P_OF0_24M2P_2MPO_ET_M0
  CLASS CORE ;
  ORIGIN 0 0 ;
  FOREIGN AOI22_X2_6T_2F_45CPP_24M0P_30M1P_OF0_24M2P_2MPO_ET_M0 0 0 ;
  SIZE 0.4050 BY 0.1440 ;
  SYMMETRY X Y ;
  SITE coresite ;
  PIN B1
    DIRECTION INPUT ;
    USE SIGNAL ;
    PORT
      LAYER M1 ;
        RECT 0.0525 0.1200 0.0675 0.0240 ;
      LAYER M0 ;
        RECT 0.0350 0.1150 0.1600 0.1010 ;
    END
  END B1
  PIN A1
    DIRECTION INPUT ;
    USE SIGNAL ;
    PORT
      LAYER M1 ;
        RECT 0.2625 0.1200 0.2775 0.0240 ;
      LAYER M0 ;
        RECT 0.2600 0.0670 0.3250 0.0530 ;
    END
  END A1
  PIN B2
    DIRECTION INPUT ;
    USE SIGNAL ;
    PORT
      LAYER M2 ;
        RECT 0.0180 0.1150 0.1920 0.1010 ;
      LAYER M1 ;
        RECT 0.0225 0.1200 0.0375 0.0240 ;
        RECT 0.1425 0.1200 0.1575 0.0240 ;
      LAYER M0 ;
        RECT 0.0125 0.0430 0.0700 0.0290 ;
        RECT 0.1400 0.0430 0.1900 0.0290 ;
    END
  END B2
  PIN A2
    DIRECTION INPUT ;
    USE SIGNAL ;
    PORT
      LAYER M2 ;
        RECT 0.1980 0.0670 0.3720 0.0530 ;
      LAYER M1 ;
        RECT 0.2025 0.1200 0.2175 0.0240 ;
        RECT 0.3525 0.1200 0.3675 0.0240 ;
      LAYER M0 ;
        RECT 0.2000 0.0670 0.2350 0.0530 ;
        RECT 0.3500 0.0670 0.3925 0.0530 ;
    END
  END A2
  PIN ZN
    DIRECTION OUTPUT ;
    USE SIGNAL ;
    PORT
      LAYER M2 ;
        RECT 0.0780 0.0430 0.1920 0.0290 ;
      LAYER M1 ;
        RECT 0.0825 0.1200 0.0975 0.0240 ;
        RECT 0.1725 0.1200 0.1875 0.0240 ;
      LAYER M0 ;
        RECT 0.0800 0.0430 0.1225 0.0290 ;
        RECT 0.1700 0.1150 0.3475 0.1010 ;
    END
  END ZN
  PIN VDD
    DIRECTION INOUT ;
    USE POWER ;
    SHAPE ABUTMENT ;
    PORT
      LAYER M0 ;
        RECT 0.0000 0.1260 0.4050 0.1620 ;
    END
  END VDD
  PIN VSS
    DIRECTION INOUT ;
    USE GROUND ;
    SHAPE ABUTMENT ;
    PORT
      LAYER M0 ;
        RECT 0.0000 -0.0180 0.4050 0.0180 ;
    END
  END VSS
  OBS
      LAYER M2 ;
        RECT 0.2280 0.0290 0.3420 0.0430 ;
      LAYER M1 ;
        RECT 0.2325 0.1200 0.2475 0.0240 ;
        RECT 0.2925 0.1200 0.3075 0.0240 ;
        RECT 0.3225 0.1200 0.3375 0.0240 ;
      LAYER V1 ;
        RECT 0.3230 0.0290 0.3370 0.0430 ;
        RECT 0.2330 0.0290 0.2470 0.0430 ;
        RECT 0.1730 0.0290 0.1870 0.0430 ;
        RECT 0.0830 0.0290 0.0970 0.0430 ;
        RECT 0.3530 0.0530 0.3670 0.0670 ;
        RECT 0.2030 0.0530 0.2170 0.0670 ;
        RECT 0.1430 0.1010 0.1570 0.1150 ;
        RECT 0.0230 0.1010 0.0370 0.1150 ;
      LAYER V0 ;
        RECT 0.3230 0.0290 0.3370 0.0430 ;
        RECT 0.2930 0.0290 0.3070 0.0430 ;
        RECT 0.2330 0.0290 0.2470 0.0430 ;
        RECT 0.1430 0.0290 0.1570 0.0430 ;
        RECT 0.0830 0.0290 0.0970 0.0430 ;
        RECT 0.0230 0.0290 0.0370 0.0430 ;
        RECT 0.3530 0.0530 0.3670 0.0670 ;
        RECT 0.2630 0.0530 0.2770 0.0670 ;
        RECT 0.2030 0.0530 0.2170 0.0670 ;
        RECT 0.2930 0.1010 0.3070 0.1150 ;
        RECT 0.1730 0.1010 0.1870 0.1150 ;
        RECT 0.0530 0.1010 0.0670 0.1150 ;
      LAYER M0 ;
        RECT 0.0125 0.0770 0.3925 0.0910 ;
        RECT 0.0575 0.0530 0.1675 0.0670 ;
        RECT 0.2000 0.0290 0.2575 0.0430 ;
        RECT 0.2825 0.0290 0.3100 0.0430 ;
        RECT 0.3200 0.0290 0.3700 0.0430 ;
  END
END AOI22_X2_6T_2F_45CPP_24M0P_30M1P_OF0_24M2P_2MPO_ET_M0

MACRO LHQ_X1_6T_2F_45CPP_24M0P_30M1P_OF0_24M2P_2MPO_ET_M0
  CLASS CORE ;
  ORIGIN 0 0 ;
  FOREIGN LHQ_X1_6T_2F_45CPP_24M0P_30M1P_OF0_24M2P_2MPO_ET_M0 0 0 ;
  SIZE 0.4500 BY 0.1440 ;
  SYMMETRY X Y ;
  SITE coresite ;
  PIN E
    DIRECTION INPUT ;
    USE SIGNAL ;
    PORT
      LAYER M0 ;
        RECT 0.0125 0.0670 0.1300 0.0530 ;
    END
  END E
  PIN D
    DIRECTION INPUT ;
    USE SIGNAL ;
    PORT
      LAYER M0 ;
        RECT 0.3500 0.0670 0.4000 0.0530 ;
    END
  END D
  PIN Q
    DIRECTION OUTPUT ;
    USE SIGNAL ;
    PORT
      LAYER M0 ;
        RECT 0.4100 0.1150 0.4375 0.1010 ;
    END
  END Q
  PIN VDD
    DIRECTION INOUT ;
    USE POWER ;
    SHAPE ABUTMENT ;
    PORT
      LAYER M0 ;
        RECT 0.0000 0.1260 0.4500 0.1620 ;
    END
  END VDD
  PIN VSS
    DIRECTION INOUT ;
    USE GROUND ;
    SHAPE ABUTMENT ;
    PORT
      LAYER M0 ;
        RECT 0.0000 -0.0180 0.4500 0.0180 ;
    END
  END VSS
  OBS
      LAYER M2 ;
        RECT 0.1680 0.0290 0.3420 0.0430 ;
      LAYER M1 ;
        RECT 0.2325 0.1200 0.2475 0.0240 ;
        RECT 0.2625 0.1200 0.2775 0.0240 ;
        RECT 0.2925 0.1200 0.3075 0.0240 ;
        RECT 0.3225 0.1200 0.3375 0.0240 ;
      LAYER V1 ;
        RECT 0.3230 0.0290 0.3370 0.0430 ;
        RECT 0.2330 0.0290 0.2470 0.0430 ;
      LAYER V0 ;
        RECT 0.2330 0.0290 0.2470 0.0430 ;
        RECT 0.2930 0.0290 0.3070 0.0430 ;
        RECT 0.2630 0.0530 0.2770 0.0670 ;
        RECT 0.2930 0.0530 0.3070 0.0670 ;
        RECT 0.2630 0.1010 0.2770 0.1150 ;
        RECT 0.3230 0.1010 0.3370 0.1150 ;
      LAYER M0 ;
        RECT 0.0125 0.1010 0.2800 0.1150 ;
        RECT 0.3050 0.1010 0.3400 0.1150 ;
        RECT 0.0125 0.0770 0.4375 0.0910 ;
        RECT 0.1400 0.0530 0.2500 0.0670 ;
        RECT 0.2600 0.0530 0.3100 0.0670 ;
        RECT 0.0125 0.0290 0.2800 0.0430 ;
        RECT 0.2900 0.0290 0.3400 0.0430 ;
  END
END LHQ_X1_6T_2F_45CPP_24M0P_30M1P_OF0_24M2P_2MPO_ET_M0

MACRO DFFHQN_X1_6T_2F_45CPP_24M0P_30M1P_OF0_24M2P_2MPO_ET_M0
  CLASS CORE ;
  ORIGIN 0 0 ;
  FOREIGN DFFHQN_X1_6T_2F_45CPP_24M0P_30M1P_OF0_24M2P_2MPO_ET_M0 0 0 ;
  SIZE 0.6300 BY 0.1440 ;
  SYMMETRY X Y ;
  SITE coresite ;
  PIN CLK
    DIRECTION INPUT ;
    USE SIGNAL ;
    PORT
      LAYER M0 ;
        RECT 0.5750 0.1150 0.6100 0.1010 ;
    END
  END CLK
  PIN D
    DIRECTION INPUT ;
    USE SIGNAL ;
    PORT
      LAYER M0 ;
        RECT 0.5300 0.0670 0.5725 0.0530 ;
    END
  END D
  PIN QN
    DIRECTION OUTPUT ;
    USE SIGNAL ;
    PORT
      LAYER M0 ;
        RECT 0.0125 0.0430 0.0400 0.0290 ;
    END
  END QN
  PIN VDD
    DIRECTION INOUT ;
    USE POWER ;
    SHAPE ABUTMENT ;
    PORT
      LAYER M0 ;
        RECT 0.0000 0.1260 0.6300 0.1620 ;
    END
  END VDD
  PIN VSS
    DIRECTION INOUT ;
    USE GROUND ;
    SHAPE ABUTMENT ;
    PORT
      LAYER M0 ;
        RECT 0.0000 -0.0180 0.6300 0.0180 ;
    END
  END VSS
  OBS
      LAYER M2 ;
        RECT 0.2280 0.0530 0.4920 0.0670 ;
      LAYER M1 ;
        RECT 0.2325 0.1200 0.2475 0.0240 ;
        RECT 0.2625 0.1200 0.2775 0.0240 ;
        RECT 0.2925 0.1200 0.3075 0.0240 ;
        RECT 0.3825 0.1200 0.3975 0.0240 ;
        RECT 0.4425 0.1200 0.4575 0.0240 ;
        RECT 0.4725 0.1200 0.4875 0.0240 ;
        RECT 0.5025 0.1200 0.5175 0.0240 ;
      LAYER V1 ;
        RECT 0.4730 0.0530 0.4870 0.0670 ;
        RECT 0.3830 0.0530 0.3970 0.0670 ;
        RECT 0.2330 0.0530 0.2470 0.0670 ;
      LAYER V0 ;
        RECT 0.2330 0.0290 0.2470 0.0430 ;
        RECT 0.2930 0.0290 0.3070 0.0430 ;
        RECT 0.4430 0.0290 0.4570 0.0430 ;
        RECT 0.4730 0.0290 0.4870 0.0430 ;
        RECT 0.4430 0.0530 0.4570 0.0670 ;
        RECT 0.5030 0.0530 0.5170 0.0670 ;
        RECT 0.2630 0.0770 0.2770 0.0910 ;
        RECT 0.2930 0.0770 0.3070 0.0910 ;
        RECT 0.2630 0.1010 0.2770 0.1150 ;
        RECT 0.3830 0.1010 0.3970 0.1150 ;
        RECT 0.5030 0.1010 0.5170 0.1150 ;
      LAYER M0 ;
        RECT 0.1475 0.1010 0.2800 0.1150 ;
        RECT 0.3050 0.1010 0.4600 0.1150 ;
        RECT 0.4850 0.1010 0.5200 0.1150 ;
        RECT 0.1025 0.0770 0.2350 0.0910 ;
        RECT 0.2600 0.0770 0.3100 0.0910 ;
        RECT 0.3500 0.0770 0.4825 0.0910 ;
        RECT 0.0350 0.0530 0.3025 0.0670 ;
        RECT 0.3275 0.0530 0.4150 0.0670 ;
        RECT 0.4400 0.0530 0.5200 0.0670 ;
        RECT 0.1700 0.0290 0.2800 0.0430 ;
        RECT 0.2900 0.0290 0.4600 0.0430 ;
        RECT 0.4700 0.0290 0.6175 0.0430 ;
  END
END DFFHQN_X1_6T_2F_45CPP_24M0P_30M1P_OF0_24M2P_2MPO_ET_M0

MACRO DFFHQN_X1_6T_2F_45CPP_24M0P_30M1P_OF15_24M2P_2MPO_ET_M0
  CLASS CORE ;
  ORIGIN 0 0 ;
  FOREIGN DFFHQN_X1_6T_2F_45CPP_24M0P_30M1P_OF15_24M2P_2MPO_ET_M0 0 0 ;
  SIZE 0.6300 BY 0.1440 ;
  SYMMETRY X Y ;
  SITE coresite ;
  PIN D
    DIRECTION INPUT ;
    USE SIGNAL ;
    PORT
      LAYER M0 ;
        RECT 0.5300 0.0910 0.5650 0.0770 ;
    END
  END D
  PIN QN
    DIRECTION OUTPUT ;
    USE SIGNAL ;
    PORT
      LAYER M0 ;
        RECT 0.0125 0.0910 0.0550 0.0770 ;
    END
  END QN
  PIN CLK
    DIRECTION INPUT ;
    USE SIGNAL ;
    PORT
      LAYER M0 ;
        RECT 0.5750 0.0430 0.6175 0.0290 ;
    END
  END CLK
  PIN VDD
    DIRECTION INOUT ;
    USE POWER ;
    SHAPE ABUTMENT ;
    PORT
      LAYER M0 ;
        RECT 0.0000 0.1260 0.6300 0.1620 ;
    END
  END VDD
  PIN VSS
    DIRECTION INOUT ;
    USE GROUND ;
    SHAPE ABUTMENT ;
    PORT
      LAYER M0 ;
        RECT 0.0000 -0.0180 0.6300 0.0180 ;
    END
  END VSS
  OBS
      LAYER M1 ;
        RECT 0.2475 0.1200 0.2625 0.0240 ;
        RECT 0.2775 0.1200 0.2925 0.0240 ;
        RECT 0.3075 0.1200 0.3225 0.0240 ;
        RECT 0.3675 0.1200 0.3825 0.0240 ;
        RECT 0.4275 0.1200 0.4425 0.0240 ;
        RECT 0.4875 0.1200 0.5025 0.0240 ;
        RECT 0.5175 0.1200 0.5325 0.0240 ;
      LAYER M2 ;
        RECT 0.2730 0.0530 0.5070 0.0670 ;
      LAYER V0 ;
        RECT 0.2480 0.0290 0.2620 0.0430 ;
        RECT 0.3680 0.0290 0.3820 0.0430 ;
        RECT 0.5180 0.0290 0.5320 0.0430 ;
        RECT 0.4280 0.0530 0.4420 0.0670 ;
        RECT 0.5180 0.0530 0.5320 0.0670 ;
        RECT 0.2480 0.0770 0.2620 0.0910 ;
        RECT 0.3080 0.0770 0.3220 0.0910 ;
        RECT 0.2780 0.1010 0.2920 0.1150 ;
        RECT 0.3080 0.1010 0.3220 0.1150 ;
        RECT 0.4280 0.1010 0.4420 0.1150 ;
        RECT 0.4880 0.1010 0.5020 0.1150 ;
      LAYER M0 ;
        RECT 0.1475 0.1010 0.2950 0.1150 ;
        RECT 0.3050 0.1010 0.4600 0.1150 ;
        RECT 0.4850 0.1010 0.5275 0.1150 ;
        RECT 0.1700 0.0770 0.3250 0.0910 ;
        RECT 0.3500 0.0770 0.4825 0.0910 ;
        RECT 0.0350 0.0530 0.3025 0.0670 ;
        RECT 0.3275 0.0530 0.4150 0.0670 ;
        RECT 0.4250 0.0530 0.6175 0.0670 ;
        RECT 0.1025 0.0290 0.2350 0.0430 ;
        RECT 0.2450 0.0290 0.2800 0.0430 ;
        RECT 0.3050 0.0290 0.4600 0.0430 ;
        RECT 0.4850 0.0290 0.5350 0.0430 ;
      LAYER V1 ;
        RECT 0.4880 0.0530 0.5020 0.0670 ;
        RECT 0.3680 0.0530 0.3820 0.0670 ;
        RECT 0.2780 0.0530 0.2920 0.0670 ;
  END
END DFFHQN_X1_6T_2F_45CPP_24M0P_30M1P_OF15_24M2P_2MPO_ET_M0

MACRO LHQ_X1_6T_2F_45CPP_24M0P_30M1P_OF15_24M2P_2MPO_ET_M0
  CLASS CORE ;
  ORIGIN 0 0 ;
  FOREIGN LHQ_X1_6T_2F_45CPP_24M0P_30M1P_OF15_24M2P_2MPO_ET_M0 0 0 ;
  SIZE 0.4500 BY 0.1440 ;
  SYMMETRY X Y ;
  SITE coresite ;
  PIN D
    DIRECTION INPUT ;
    USE SIGNAL ;
    PORT
      LAYER M0 ;
        RECT 0.3500 0.0670 0.4375 0.0530 ;
    END
  END D
  PIN E
    DIRECTION INPUT ;
    USE SIGNAL ;
    PORT
      LAYER M0 ;
        RECT 0.0125 0.0910 0.1000 0.0770 ;
    END
  END E
  PIN Q
    DIRECTION OUTPUT ;
    USE SIGNAL ;
    PORT
      LAYER M0 ;
        RECT 0.3650 0.1155 0.4375 0.1015 ;
    END
  END Q
  PIN VDD
    DIRECTION INOUT ;
    USE POWER ;
    SHAPE ABUTMENT ;
    PORT
      LAYER M0 ;
        RECT 0.0000 0.1260 0.4500 0.1620 ;
    END
  END VDD
  PIN VSS
    DIRECTION INOUT ;
    USE GROUND ;
    SHAPE ABUTMENT ;
    PORT
      LAYER M0 ;
        RECT 0.0000 -0.0180 0.4500 0.0180 ;
    END
  END VSS
  OBS
      LAYER M1 ;
        RECT 0.1875 0.1200 0.2025 0.0240 ;
        RECT 0.2475 0.1200 0.2625 0.0240 ;
        RECT 0.3075 0.1200 0.3225 0.0240 ;
        RECT 0.3375 0.1200 0.3525 0.0240 ;
      LAYER M2 ;
        RECT 0.1830 0.0290 0.3570 0.0430 ;
      LAYER V0 ;
        RECT 0.2480 0.0290 0.2620 0.0430 ;
        RECT 0.3380 0.0290 0.3520 0.0430 ;
        RECT 0.2480 0.0530 0.2620 0.0670 ;
        RECT 0.3080 0.0530 0.3220 0.0670 ;
        RECT 0.1880 0.1010 0.2020 0.1150 ;
        RECT 0.3080 0.1010 0.3220 0.1150 ;
      LAYER M0 ;
        RECT 0.0125 0.1010 0.2800 0.1150 ;
        RECT 0.3050 0.1010 0.3400 0.1150 ;
        RECT 0.1700 0.0770 0.4150 0.0910 ;
        RECT 0.0350 0.0530 0.3250 0.0670 ;
        RECT 0.1475 0.0290 0.2350 0.0430 ;
        RECT 0.2450 0.0290 0.2800 0.0430 ;
        RECT 0.3050 0.0290 0.3550 0.0430 ;
      LAYER V1 ;
        RECT 0.3380 0.0290 0.3520 0.0430 ;
        RECT 0.1880 0.0290 0.2020 0.0430 ;
  END
END LHQ_X1_6T_2F_45CPP_24M0P_30M1P_OF15_24M2P_2MPO_ET_M0

MACRO AOI22_X2_6T_2F_45CPP_24M0P_30M1P_OF15_24M2P_2MPO_ET_M0
  CLASS CORE ;
  ORIGIN 0 0 ;
  FOREIGN AOI22_X2_6T_2F_45CPP_24M0P_30M1P_OF15_24M2P_2MPO_ET_M0 0 0 ;
  SIZE 0.4050 BY 0.1440 ;
  SYMMETRY X Y ;
  SITE coresite ;
  PIN A1
    DIRECTION INPUT ;
    USE SIGNAL ;
    PORT
      LAYER M2 ;
        RECT 0.2130 0.1150 0.3570 0.1010 ;
      LAYER M1 ;
        RECT 0.2175 0.1200 0.2325 0.0240 ;
        RECT 0.3375 0.1200 0.3525 0.0240 ;
      LAYER M0 ;
        RECT 0.1850 0.0670 0.2350 0.0530 ;
        RECT 0.3350 0.0670 0.3700 0.0530 ;
    END
  END A1
  PIN ZN
    DIRECTION OUTPUT ;
    USE SIGNAL ;
    PORT
      LAYER M2 ;
        RECT 0.0330 0.0430 0.3270 0.0290 ;
      LAYER M1 ;
        RECT 0.0375 0.1200 0.0525 0.0240 ;
        RECT 0.1875 0.1200 0.2025 0.0240 ;
        RECT 0.3075 0.1200 0.3225 0.0240 ;
      LAYER M0 ;
        RECT 0.0125 0.0430 0.0550 0.0290 ;
        RECT 0.1850 0.0430 0.2125 0.0290 ;
        RECT 0.2375 0.1150 0.3850 0.1010 ;
    END
  END ZN
  PIN B1
    DIRECTION INPUT ;
    USE SIGNAL ;
    PORT
      LAYER M0 ;
        RECT 0.0125 0.1150 0.1900 0.1010 ;
    END
  END B1
  PIN A2
    DIRECTION INPUT ;
    USE SIGNAL ;
    PORT
      LAYER M0 ;
        RECT 0.2450 0.0670 0.3250 0.0530 ;
    END
  END A2
  PIN B2
    DIRECTION INPUT ;
    USE SIGNAL ;
    PORT
      LAYER M0 ;
        RECT 0.0800 0.0430 0.1750 0.0290 ;
    END
  END B2
  PIN VDD
    DIRECTION INOUT ;
    USE POWER ;
    SHAPE ABUTMENT ;
    PORT
      LAYER M0 ;
        RECT 0.0000 0.1260 0.4050 0.1620 ;
    END
  END VDD
  PIN VSS
    DIRECTION INOUT ;
    USE GROUND ;
    SHAPE ABUTMENT ;
    PORT
      LAYER M0 ;
        RECT 0.0000 -0.0180 0.4050 0.0180 ;
    END
  END VSS
  OBS
      LAYER M1 ;
        RECT 0.3675 0.1200 0.3825 0.0240 ;
      LAYER V0 ;
        RECT 0.0380 0.0290 0.0520 0.0430 ;
        RECT 0.1880 0.0290 0.2020 0.0430 ;
        RECT 0.3680 0.0290 0.3820 0.0430 ;
        RECT 0.2180 0.0530 0.2320 0.0670 ;
        RECT 0.3380 0.0530 0.3520 0.0670 ;
        RECT 0.3080 0.1010 0.3220 0.1150 ;
        RECT 0.3680 0.1010 0.3820 0.1150 ;
      LAYER M0 ;
        RECT 0.0125 0.0770 0.3925 0.0910 ;
        RECT 0.0575 0.0530 0.1675 0.0670 ;
        RECT 0.2375 0.0290 0.3475 0.0430 ;
        RECT 0.3650 0.0290 0.3925 0.0430 ;
      LAYER V1 ;
        RECT 0.3080 0.0290 0.3220 0.0430 ;
        RECT 0.1880 0.0290 0.2020 0.0430 ;
        RECT 0.0380 0.0290 0.0520 0.0430 ;
        RECT 0.3380 0.1010 0.3520 0.1150 ;
        RECT 0.2180 0.1010 0.2320 0.1150 ;
  END
END AOI22_X2_6T_2F_45CPP_24M0P_30M1P_OF15_24M2P_2MPO_ET_M0

MACRO AOI21_X2_6T_2F_45CPP_24M0P_30M1P_OF15_24M2P_2MPO_ET_M0
  CLASS CORE ;
  ORIGIN 0 0 ;
  FOREIGN AOI21_X2_6T_2F_45CPP_24M0P_30M1P_OF15_24M2P_2MPO_ET_M0 0 0 ;
  SIZE 0.3150 BY 0.1440 ;
  SYMMETRY X Y ;
  SITE coresite ;
  PIN ZN
    DIRECTION OUTPUT ;
    USE SIGNAL ;
    PORT
      LAYER M1 ;
        RECT 0.1875 0.1200 0.2025 0.0240 ;
      LAYER M0 ;
        RECT 0.0650 0.1150 0.2575 0.1010 ;
        RECT 0.1850 0.0430 0.2125 0.0290 ;
    END
  END ZN
  PIN A2
    DIRECTION INPUT ;
    USE SIGNAL ;
    PORT
      LAYER M2 ;
        RECT 0.0930 0.1150 0.2970 0.1010 ;
      LAYER M1 ;
        RECT 0.0975 0.1200 0.1125 0.0240 ;
        RECT 0.2775 0.1200 0.2925 0.0240 ;
      LAYER M0 ;
        RECT 0.0950 0.0670 0.1450 0.0530 ;
        RECT 0.2600 0.0670 0.2950 0.0530 ;
    END
  END A2
  PIN A1
    DIRECTION INPUT ;
    USE SIGNAL ;
    PORT
      LAYER M0 ;
        RECT 0.1550 0.0670 0.2350 0.0530 ;
    END
  END A1
  PIN B
    DIRECTION INPUT ;
    USE SIGNAL ;
    PORT
      LAYER M0 ;
        RECT 0.0125 0.0430 0.1150 0.0290 ;
    END
  END B
  PIN VDD
    DIRECTION INOUT ;
    USE POWER ;
    SHAPE ABUTMENT ;
    PORT
      LAYER M0 ;
        RECT 0.0000 0.1260 0.3150 0.1620 ;
    END
  END VDD
  PIN VSS
    DIRECTION INOUT ;
    USE GROUND ;
    SHAPE ABUTMENT ;
    PORT
      LAYER M0 ;
        RECT 0.0000 -0.0180 0.3150 0.0180 ;
    END
  END VSS
  OBS
      LAYER M1 ;
        RECT 0.0675 0.1200 0.0825 0.0240 ;
        RECT 0.1275 0.1200 0.1425 0.0240 ;
        RECT 0.2475 0.1200 0.2625 0.0240 ;
      LAYER M2 ;
        RECT 0.1230 0.0290 0.2670 0.0430 ;
      LAYER V0 ;
        RECT 0.1280 0.0290 0.1420 0.0430 ;
        RECT 0.1880 0.0290 0.2020 0.0430 ;
        RECT 0.2480 0.0290 0.2620 0.0430 ;
        RECT 0.0680 0.0530 0.0820 0.0670 ;
        RECT 0.0980 0.0530 0.1120 0.0670 ;
        RECT 0.2780 0.0530 0.2920 0.0670 ;
        RECT 0.0680 0.1010 0.0820 0.1150 ;
        RECT 0.1880 0.1010 0.2020 0.1150 ;
      LAYER M0 ;
        RECT 0.0125 0.0770 0.3025 0.0910 ;
        RECT 0.0575 0.0530 0.0850 0.0670 ;
        RECT 0.2375 0.0290 0.2650 0.0430 ;
        RECT 0.1250 0.0290 0.1675 0.0430 ;
      LAYER V1 ;
        RECT 0.2480 0.0290 0.2620 0.0430 ;
        RECT 0.1280 0.0290 0.1420 0.0430 ;
        RECT 0.2780 0.1010 0.2920 0.1150 ;
        RECT 0.0980 0.1010 0.1120 0.1150 ;
  END
END AOI21_X2_6T_2F_45CPP_24M0P_30M1P_OF15_24M2P_2MPO_ET_M0

MACRO OAI22_X2_6T_2F_45CPP_24M0P_30M1P_OF15_24M2P_2MPO_ET_M0
  CLASS CORE ;
  ORIGIN 0 0 ;
  FOREIGN OAI22_X2_6T_2F_45CPP_24M0P_30M1P_OF15_24M2P_2MPO_ET_M0 0 0 ;
  SIZE 0.4500 BY 0.1440 ;
  SYMMETRY X Y ;
  SITE coresite ;
  PIN ZN
    DIRECTION OUTPUT ;
    USE SIGNAL ;
    PORT
      LAYER M1 ;
        RECT 0.0375 0.1200 0.0525 0.0240 ;
      LAYER M0 ;
        RECT 0.0125 0.1150 0.0550 0.1010 ;
    END
  END ZN
  PIN ZN
    DIRECTION OUTPUT ;
    USE SIGNAL ;
    PORT
      LAYER M1 ;
        RECT 0.2175 0.1200 0.2325 0.0240 ;
      LAYER M0 ;
        RECT 0.2150 0.0670 0.3925 0.0530 ;
        RECT 0.1925 0.0910 0.2350 0.0770 ;
    END
  END ZN
  PIN ZN
    DIRECTION OUTPUT ;
    USE SIGNAL ;
    PORT
      LAYER M2 ;
        RECT 0.0330 0.0430 0.2370 0.0290 ;
    END
  END ZN
  PIN B1
    DIRECTION INPUT ;
    USE SIGNAL ;
    PORT
      LAYER M0 ;
        RECT 0.0350 0.0670 0.1900 0.0530 ;
    END
  END B1
  PIN A2
    DIRECTION INPUT ;
    USE SIGNAL ;
    PORT
      LAYER M0 ;
        RECT 0.2600 0.0910 0.3250 0.0770 ;
    END
  END A2
  PIN A1
    DIRECTION INPUT ;
    USE SIGNAL ;
    PORT
      LAYER M0 ;
        RECT 0.3500 0.0910 0.4150 0.0770 ;
    END
  END A1
  PIN B2
    DIRECTION INPUT ;
    USE SIGNAL ;
    PORT
      LAYER M0 ;
        RECT 0.0800 0.1150 0.1450 0.1010 ;
    END
  END B2
  PIN VDD
    DIRECTION INOUT ;
    USE POWER ;
    SHAPE ABUTMENT ;
    PORT
      LAYER M0 ;
        RECT 0.0000 0.1260 0.4500 0.1620 ;
    END
  END VDD
  PIN VSS
    DIRECTION INOUT ;
    USE GROUND ;
    SHAPE ABUTMENT ;
    PORT
      LAYER M0 ;
        RECT 0.0000 -0.0180 0.4500 0.0180 ;
    END
  END VSS
  OBS
      LAYER M0 ;
        RECT 0.0575 0.0290 0.4375 0.0430 ;
        RECT 0.0575 0.0770 0.1675 0.0910 ;
        RECT 0.2375 0.1010 0.4375 0.1150 ;
      LAYER V0 ;
        RECT 0.2180 0.0530 0.2320 0.0670 ;
        RECT 0.2180 0.0770 0.2320 0.0910 ;
        RECT 0.0380 0.1010 0.0520 0.1150 ;
      LAYER V1 ;
        RECT 0.0380 0.0290 0.0520 0.0430 ;
        RECT 0.2180 0.0290 0.2320 0.0430 ;
  END
END OAI22_X2_6T_2F_45CPP_24M0P_30M1P_OF15_24M2P_2MPO_ET_M0

MACRO OAI21_X2_6T_2F_45CPP_24M0P_30M1P_OF15_24M2P_2MPO_ET_M0
  CLASS CORE ;
  ORIGIN 0 0 ;
  FOREIGN OAI21_X2_6T_2F_45CPP_24M0P_30M1P_OF15_24M2P_2MPO_ET_M0 0 0 ;
  SIZE 0.3150 BY 0.1440 ;
  SYMMETRY X Y ;
  SITE coresite ;
  PIN ZN
    DIRECTION OUTPUT ;
    USE SIGNAL ;
    PORT
      LAYER M2 ;
        RECT 0.0930 0.1150 0.2370 0.1010 ;
      LAYER M1 ;
        RECT 0.0975 0.1200 0.1125 0.0240 ;
        RECT 0.2175 0.1200 0.2325 0.0240 ;
      LAYER M0 ;
        RECT 0.0125 0.0430 0.1225 0.0290 ;
        RECT 0.1475 0.1150 0.2650 0.1010 ;
    END
  END ZN
  PIN A2
    DIRECTION INPUT ;
    USE SIGNAL ;
    PORT
      LAYER M0 ;
        RECT 0.0125 0.0910 0.1150 0.0770 ;
    END
  END A2
  PIN A1
    DIRECTION INPUT ;
    USE SIGNAL ;
    PORT
      LAYER M0 ;
        RECT 0.1250 0.0910 0.2800 0.0770 ;
    END
  END A1
  PIN B
    DIRECTION INPUT ;
    USE SIGNAL ;
    PORT
      LAYER M0 ;
        RECT 0.1475 0.0430 0.2350 0.0290 ;
    END
  END B
  PIN VDD
    DIRECTION INOUT ;
    USE POWER ;
    SHAPE ABUTMENT ;
    PORT
      LAYER M0 ;
        RECT 0.0000 0.1260 0.3150 0.1620 ;
    END
  END VDD
  PIN VSS
    DIRECTION INOUT ;
    USE GROUND ;
    SHAPE ABUTMENT ;
    PORT
      LAYER M0 ;
        RECT 0.0000 -0.0180 0.3150 0.0180 ;
    END
  END VSS
  OBS
      LAYER M1 ;
        RECT 0.0375 0.1200 0.0525 0.0240 ;
        RECT 0.2475 0.1200 0.2625 0.0240 ;
        RECT 0.2775 0.1200 0.2925 0.0240 ;
      LAYER M2 ;
        RECT 0.0330 0.0530 0.2970 0.0670 ;
      LAYER V0 ;
        RECT 0.0980 0.0290 0.1120 0.0430 ;
        RECT 0.2480 0.0290 0.2620 0.0430 ;
        RECT 0.0380 0.1010 0.0520 0.1150 ;
        RECT 0.2180 0.1010 0.2320 0.1150 ;
        RECT 0.2480 0.1010 0.2620 0.1150 ;
        RECT 0.2780 0.1010 0.2920 0.1150 ;
      LAYER M0 ;
        RECT 0.0125 0.1010 0.1225 0.1150 ;
        RECT 0.2750 0.1010 0.3025 0.1150 ;
        RECT 0.0575 0.0530 0.3025 0.0670 ;
        RECT 0.2450 0.0290 0.3025 0.0430 ;
      LAYER V1 ;
        RECT 0.2780 0.0530 0.2920 0.0670 ;
        RECT 0.0380 0.0530 0.0520 0.0670 ;
        RECT 0.2180 0.1010 0.2320 0.1150 ;
        RECT 0.0980 0.1010 0.1120 0.1150 ;
  END
END OAI21_X2_6T_2F_45CPP_24M0P_30M1P_OF15_24M2P_2MPO_ET_M0

MACRO OAI22_X1_6T_2F_45CPP_24M0P_30M1P_OF15_24M2P_2MPO_ET_M0
  CLASS CORE ;
  ORIGIN 0 0 ;
  FOREIGN OAI22_X1_6T_2F_45CPP_24M0P_30M1P_OF15_24M2P_2MPO_ET_M0 0 0 ;
  SIZE 0.2250 BY 0.1440 ;
  SYMMETRY X Y ;
  SITE coresite ;
  PIN ZN
    DIRECTION OUTPUT ;
    USE SIGNAL ;
    PORT
      LAYER M1 ;
        RECT 0.1275 0.1200 0.1425 0.0240 ;
      LAYER M0 ;
        RECT 0.1025 0.1150 0.1450 0.1010 ;
        RECT 0.1250 0.0430 0.1675 0.0290 ;
    END
  END ZN
  PIN A2
    DIRECTION INPUT ;
    USE SIGNAL ;
    PORT
      LAYER M0 ;
        RECT 0.1700 0.1150 0.2125 0.1010 ;
    END
  END A2
  PIN A1
    DIRECTION INPUT ;
    USE SIGNAL ;
    PORT
      LAYER M0 ;
        RECT 0.0350 0.0910 0.1750 0.0770 ;
    END
  END A1
  PIN B2
    DIRECTION INPUT ;
    USE SIGNAL ;
    PORT
      LAYER M0 ;
        RECT 0.0125 0.0430 0.0550 0.0290 ;
    END
  END B2
  PIN B1
    DIRECTION INPUT ;
    USE SIGNAL ;
    PORT
      LAYER M0 ;
        RECT 0.0650 0.0430 0.1000 0.0290 ;
    END
  END B1
  PIN VDD
    DIRECTION INOUT ;
    USE POWER ;
    SHAPE ABUTMENT ;
    PORT
      LAYER M0 ;
        RECT 0.0000 0.1260 0.2250 0.1620 ;
    END
  END VDD
  PIN VSS
    DIRECTION INOUT ;
    USE GROUND ;
    SHAPE ABUTMENT ;
    PORT
      LAYER M0 ;
        RECT 0.0000 -0.0180 0.2250 0.0180 ;
    END
  END VSS
  OBS
      LAYER M0 ;
        RECT 0.0125 0.0530 0.2125 0.0670 ;
      LAYER V0 ;
        RECT 0.1280 0.0290 0.1420 0.0430 ;
        RECT 0.1280 0.1010 0.1420 0.1150 ;
  END
END OAI22_X1_6T_2F_45CPP_24M0P_30M1P_OF15_24M2P_2MPO_ET_M0

MACRO AOI22_X1_6T_2F_45CPP_24M0P_30M1P_OF15_24M2P_2MPO_ET_M0
  CLASS CORE ;
  ORIGIN 0 0 ;
  FOREIGN AOI22_X1_6T_2F_45CPP_24M0P_30M1P_OF15_24M2P_2MPO_ET_M0 0 0 ;
  SIZE 0.2250 BY 0.1440 ;
  SYMMETRY X Y ;
  SITE coresite ;
  PIN ZN
    DIRECTION OUTPUT ;
    USE SIGNAL ;
    PORT
      LAYER M1 ;
        RECT 0.1275 0.1200 0.1425 0.0240 ;
      LAYER M0 ;
        RECT 0.1250 0.1150 0.1675 0.1010 ;
        RECT 0.1025 0.0430 0.1450 0.0290 ;
    END
  END ZN
  PIN B1
    DIRECTION INPUT ;
    USE SIGNAL ;
    PORT
      LAYER M0 ;
        RECT 0.0125 0.1150 0.1000 0.1010 ;
    END
  END B1
  PIN A1
    DIRECTION INPUT ;
    USE SIGNAL ;
    PORT
      LAYER M0 ;
        RECT 0.1250 0.0670 0.2125 0.0530 ;
    END
  END A1
  PIN B2
    DIRECTION INPUT ;
    USE SIGNAL ;
    PORT
      LAYER M0 ;
        RECT 0.0350 0.0430 0.0850 0.0290 ;
    END
  END B2
  PIN A2
    DIRECTION INPUT ;
    USE SIGNAL ;
    PORT
      LAYER M0 ;
        RECT 0.1550 0.0430 0.1900 0.0290 ;
    END
  END A2
  PIN VDD
    DIRECTION INOUT ;
    USE POWER ;
    SHAPE ABUTMENT ;
    PORT
      LAYER M0 ;
        RECT 0.0000 0.1260 0.2250 0.1620 ;
    END
  END VDD
  PIN VSS
    DIRECTION INOUT ;
    USE GROUND ;
    SHAPE ABUTMENT ;
    PORT
      LAYER M0 ;
        RECT 0.0000 -0.0180 0.2250 0.0180 ;
    END
  END VSS
  OBS
      LAYER M0 ;
        RECT 0.0125 0.0770 0.2125 0.0910 ;
      LAYER V0 ;
        RECT 0.1280 0.0290 0.1420 0.0430 ;
        RECT 0.1280 0.1010 0.1420 0.1150 ;
  END
END AOI22_X1_6T_2F_45CPP_24M0P_30M1P_OF15_24M2P_2MPO_ET_M0

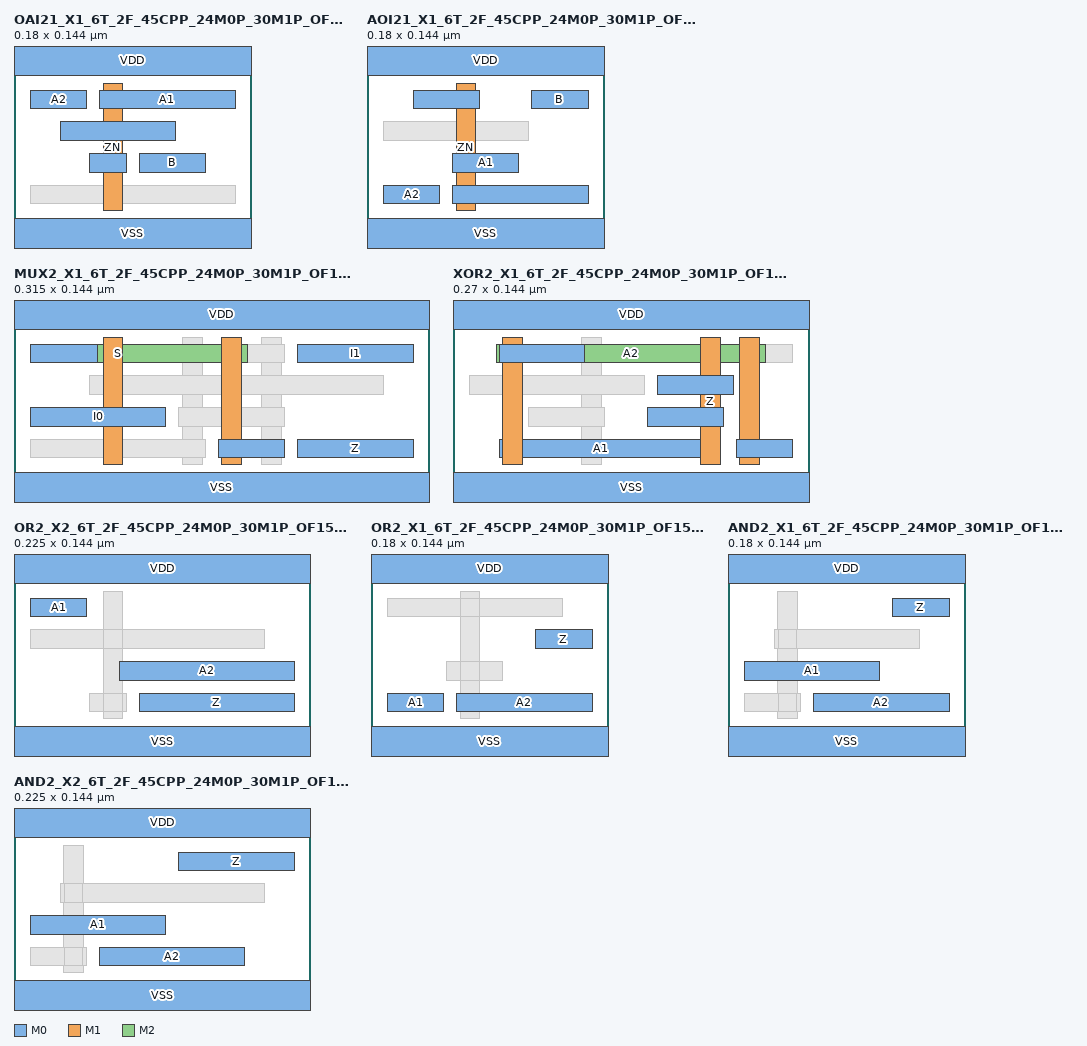
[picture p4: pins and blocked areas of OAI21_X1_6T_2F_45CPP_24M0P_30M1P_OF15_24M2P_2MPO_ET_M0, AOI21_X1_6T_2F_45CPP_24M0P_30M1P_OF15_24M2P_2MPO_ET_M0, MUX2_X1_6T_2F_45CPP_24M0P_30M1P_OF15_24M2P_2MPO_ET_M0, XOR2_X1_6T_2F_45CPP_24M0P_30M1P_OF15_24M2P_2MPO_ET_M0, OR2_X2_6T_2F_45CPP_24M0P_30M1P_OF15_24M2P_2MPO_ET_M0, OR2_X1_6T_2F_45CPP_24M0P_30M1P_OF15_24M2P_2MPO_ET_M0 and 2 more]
MACRO OAI21_X1_6T_2F_45CPP_24M0P_30M1P_OF15_24M2P_2MPO_ET_M0
  CLASS CORE ;
  ORIGIN 0 0 ;
  FOREIGN OAI21_X1_6T_2F_45CPP_24M0P_30M1P_OF15_24M2P_2MPO_ET_M0 0 0 ;
  SIZE 0.1800 BY 0.1440 ;
  SYMMETRY X Y ;
  SITE coresite ;
  PIN ZN
    DIRECTION OUTPUT ;
    USE SIGNAL ;
    PORT
      LAYER M1 ;
        RECT 0.0675 0.1200 0.0825 0.0240 ;
      LAYER M0 ;
        RECT 0.0350 0.0910 0.1225 0.0770 ;
        RECT 0.0575 0.0670 0.0850 0.0530 ;
    END
  END ZN
  PIN A2
    DIRECTION INPUT ;
    USE SIGNAL ;
    PORT
      LAYER M0 ;
        RECT 0.0125 0.1150 0.0550 0.1010 ;
    END
  END A2
  PIN A1
    DIRECTION INPUT ;
    USE SIGNAL ;
    PORT
      LAYER M0 ;
        RECT 0.0650 0.1150 0.1675 0.1010 ;
    END
  END A1
  PIN B
    DIRECTION INPUT ;
    USE SIGNAL ;
    PORT
      LAYER M0 ;
        RECT 0.0950 0.0670 0.1450 0.0530 ;
    END
  END B
  PIN VDD
    DIRECTION INOUT ;
    USE POWER ;
    SHAPE ABUTMENT ;
    PORT
      LAYER M0 ;
        RECT 0.0000 0.1260 0.1800 0.1620 ;
    END
  END VDD
  PIN VSS
    DIRECTION INOUT ;
    USE GROUND ;
    SHAPE ABUTMENT ;
    PORT
      LAYER M0 ;
        RECT 0.0000 -0.0180 0.1800 0.0180 ;
    END
  END VSS
  OBS
      LAYER M0 ;
        RECT 0.0125 0.0290 0.1675 0.0430 ;
      LAYER V0 ;
        RECT 0.0680 0.0530 0.0820 0.0670 ;
        RECT 0.0680 0.0770 0.0820 0.0910 ;
  END
END OAI21_X1_6T_2F_45CPP_24M0P_30M1P_OF15_24M2P_2MPO_ET_M0

MACRO AOI21_X1_6T_2F_45CPP_24M0P_30M1P_OF15_24M2P_2MPO_ET_M0
  CLASS CORE ;
  ORIGIN 0 0 ;
  FOREIGN AOI21_X1_6T_2F_45CPP_24M0P_30M1P_OF15_24M2P_2MPO_ET_M0 0 0 ;
  SIZE 0.1800 BY 0.1440 ;
  SYMMETRY X Y ;
  SITE coresite ;
  PIN ZN
    DIRECTION OUTPUT ;
    USE SIGNAL ;
    PORT
      LAYER M1 ;
        RECT 0.0675 0.1200 0.0825 0.0240 ;
      LAYER M0 ;
        RECT 0.0350 0.1150 0.0850 0.1010 ;
        RECT 0.0650 0.0430 0.1675 0.0290 ;
    END
  END ZN
  PIN A1
    DIRECTION INPUT ;
    USE SIGNAL ;
    PORT
      LAYER M0 ;
        RECT 0.0650 0.0670 0.1150 0.0530 ;
    END
  END A1
  PIN B
    DIRECTION INPUT ;
    USE SIGNAL ;
    PORT
      LAYER M0 ;
        RECT 0.1250 0.1150 0.1675 0.1010 ;
    END
  END B
  PIN A2
    DIRECTION INPUT ;
    USE SIGNAL ;
    PORT
      LAYER M0 ;
        RECT 0.0125 0.0430 0.0550 0.0290 ;
    END
  END A2
  PIN VDD
    DIRECTION INOUT ;
    USE POWER ;
    SHAPE ABUTMENT ;
    PORT
      LAYER M0 ;
        RECT 0.0000 0.1260 0.1800 0.1620 ;
    END
  END VDD
  PIN VSS
    DIRECTION INOUT ;
    USE GROUND ;
    SHAPE ABUTMENT ;
    PORT
      LAYER M0 ;
        RECT 0.0000 -0.0180 0.1800 0.0180 ;
    END
  END VSS
  OBS
      LAYER M0 ;
        RECT 0.0125 0.0770 0.1225 0.0910 ;
      LAYER V0 ;
        RECT 0.0680 0.0290 0.0820 0.0430 ;
        RECT 0.0680 0.1010 0.0820 0.1150 ;
  END
END AOI21_X1_6T_2F_45CPP_24M0P_30M1P_OF15_24M2P_2MPO_ET_M0

MACRO MUX2_X1_6T_2F_45CPP_24M0P_30M1P_OF15_24M2P_2MPO_ET_M0
  CLASS CORE ;
  ORIGIN 0 0 ;
  FOREIGN MUX2_X1_6T_2F_45CPP_24M0P_30M1P_OF15_24M2P_2MPO_ET_M0 0 0 ;
  SIZE 0.3150 BY 0.1440 ;
  SYMMETRY X Y ;
  SITE coresite ;
  PIN S
    DIRECTION INPUT ;
    USE SIGNAL ;
    PORT
      LAYER M2 ;
        RECT 0.0630 0.1150 0.1770 0.1010 ;
      LAYER M1 ;
        RECT 0.0675 0.1200 0.0825 0.0240 ;
        RECT 0.1575 0.1200 0.1725 0.0240 ;
      LAYER M0 ;
        RECT 0.0125 0.1150 0.1450 0.1010 ;
        RECT 0.1550 0.0430 0.2050 0.0290 ;
    END
  END S
  PIN I0
    DIRECTION INPUT ;
    USE SIGNAL ;
    PORT
      LAYER M0 ;
        RECT 0.0125 0.0670 0.1150 0.0530 ;
    END
  END I0
  PIN I1
    DIRECTION INPUT ;
    USE SIGNAL ;
    PORT
      LAYER M0 ;
        RECT 0.2150 0.1150 0.3025 0.1010 ;
    END
  END I1
  PIN Z
    DIRECTION OUTPUT ;
    USE SIGNAL ;
    PORT
      LAYER M0 ;
        RECT 0.2150 0.0430 0.3025 0.0290 ;
    END
  END Z
  PIN VDD
    DIRECTION INOUT ;
    USE POWER ;
    SHAPE ABUTMENT ;
    PORT
      LAYER M0 ;
        RECT 0.0000 0.1260 0.3150 0.1620 ;
    END
  END VDD
  PIN VSS
    DIRECTION INOUT ;
    USE GROUND ;
    SHAPE ABUTMENT ;
    PORT
      LAYER M0 ;
        RECT 0.0000 -0.0180 0.3150 0.0180 ;
    END
  END VSS
  OBS
      LAYER M1 ;
        RECT 0.1275 0.1200 0.1425 0.0240 ;
        RECT 0.1875 0.1200 0.2025 0.0240 ;
      LAYER V0 ;
        RECT 0.1280 0.0290 0.1420 0.0430 ;
        RECT 0.1580 0.0290 0.1720 0.0430 ;
        RECT 0.1280 0.0530 0.1420 0.0670 ;
        RECT 0.1880 0.0530 0.2020 0.0670 ;
        RECT 0.0680 0.1010 0.0820 0.1150 ;
        RECT 0.1880 0.1010 0.2020 0.1150 ;
      LAYER M0 ;
        RECT 0.1700 0.1010 0.2050 0.1150 ;
        RECT 0.0575 0.0770 0.2800 0.0910 ;
        RECT 0.1250 0.0530 0.2050 0.0670 ;
        RECT 0.0125 0.0290 0.1450 0.0430 ;
      LAYER V1 ;
        RECT 0.1580 0.1010 0.1720 0.1150 ;
        RECT 0.0680 0.1010 0.0820 0.1150 ;
  END
END MUX2_X1_6T_2F_45CPP_24M0P_30M1P_OF15_24M2P_2MPO_ET_M0

MACRO XOR2_X1_6T_2F_45CPP_24M0P_30M1P_OF15_24M2P_2MPO_ET_M0
  CLASS CORE ;
  ORIGIN 0 0 ;
  FOREIGN XOR2_X1_6T_2F_45CPP_24M0P_30M1P_OF15_24M2P_2MPO_ET_M0 0 0 ;
  SIZE 0.2700 BY 0.1440 ;
  SYMMETRY X Y ;
  SITE coresite ;
  PIN Z
    DIRECTION OUTPUT ;
    USE SIGNAL ;
    PORT
      LAYER M1 ;
        RECT 0.1875 0.1200 0.2025 0.0240 ;
      LAYER M0 ;
        RECT 0.1550 0.0910 0.2125 0.0770 ;
        RECT 0.1475 0.0670 0.2050 0.0530 ;
    END
  END Z
  PIN A2
    DIRECTION INPUT ;
    USE SIGNAL ;
    PORT
      LAYER M2 ;
        RECT 0.0330 0.1150 0.2370 0.1010 ;
      LAYER M1 ;
        RECT 0.0375 0.1200 0.0525 0.0240 ;
        RECT 0.2175 0.1200 0.2325 0.0240 ;
      LAYER M0 ;
        RECT 0.0350 0.1150 0.1000 0.1010 ;
        RECT 0.2150 0.0430 0.2575 0.0290 ;
    END
  END A2
  PIN A1
    DIRECTION INPUT ;
    USE SIGNAL ;
    PORT
      LAYER M0 ;
        RECT 0.0350 0.0430 0.1900 0.0290 ;
    END
  END A1
  PIN VDD
    DIRECTION INOUT ;
    USE POWER ;
    SHAPE ABUTMENT ;
    PORT
      LAYER M0 ;
        RECT 0.0000 0.1260 0.2700 0.1620 ;
    END
  END VDD
  PIN VSS
    DIRECTION INOUT ;
    USE GROUND ;
    SHAPE ABUTMENT ;
    PORT
      LAYER M0 ;
        RECT 0.0000 -0.0180 0.2700 0.0180 ;
    END
  END VSS
  OBS
      LAYER M1 ;
        RECT 0.0975 0.1200 0.1125 0.0240 ;
      LAYER V0 ;
        RECT 0.2180 0.0290 0.2320 0.0430 ;
        RECT 0.0980 0.0530 0.1120 0.0670 ;
        RECT 0.1880 0.0530 0.2020 0.0670 ;
        RECT 0.0980 0.0770 0.1120 0.0910 ;
        RECT 0.1880 0.0770 0.2020 0.0910 ;
        RECT 0.0380 0.1010 0.0520 0.1150 ;
      LAYER M0 ;
        RECT 0.1475 0.1010 0.2575 0.1150 ;
        RECT 0.0125 0.0770 0.1450 0.0910 ;
        RECT 0.0575 0.0530 0.1150 0.0670 ;
      LAYER V1 ;
        RECT 0.2180 0.1010 0.2320 0.1150 ;
        RECT 0.0380 0.1010 0.0520 0.1150 ;
  END
END XOR2_X1_6T_2F_45CPP_24M0P_30M1P_OF15_24M2P_2MPO_ET_M0

MACRO OR2_X2_6T_2F_45CPP_24M0P_30M1P_OF15_24M2P_2MPO_ET_M0
  CLASS CORE ;
  ORIGIN 0 0 ;
  FOREIGN OR2_X2_6T_2F_45CPP_24M0P_30M1P_OF15_24M2P_2MPO_ET_M0 0 0 ;
  SIZE 0.2250 BY 0.1440 ;
  SYMMETRY X Y ;
  SITE coresite ;
  PIN A2
    DIRECTION INPUT ;
    USE SIGNAL ;
    PORT
      LAYER M0 ;
        RECT 0.0800 0.0670 0.2125 0.0530 ;
    END
  END A2
  PIN Z
    DIRECTION OUTPUT ;
    USE SIGNAL ;
    PORT
      LAYER M0 ;
        RECT 0.0950 0.0430 0.2125 0.0290 ;
    END
  END Z
  PIN A1
    DIRECTION INPUT ;
    USE SIGNAL ;
    PORT
      LAYER M0 ;
        RECT 0.0125 0.1150 0.0550 0.1010 ;
    END
  END A1
  PIN VDD
    DIRECTION INOUT ;
    USE POWER ;
    SHAPE ABUTMENT ;
    PORT
      LAYER M0 ;
        RECT 0.0000 0.1260 0.2250 0.1620 ;
    END
  END VDD
  PIN VSS
    DIRECTION INOUT ;
    USE GROUND ;
    SHAPE ABUTMENT ;
    PORT
      LAYER M0 ;
        RECT 0.0000 -0.0180 0.2250 0.0180 ;
    END
  END VSS
  OBS
      LAYER M1 ;
        RECT 0.0675 0.1200 0.0825 0.0240 ;
      LAYER M0 ;
        RECT 0.0125 0.0770 0.1900 0.0910 ;
        RECT 0.0575 0.0290 0.0850 0.0430 ;
      LAYER V0 ;
        RECT 0.0680 0.0290 0.0820 0.0430 ;
        RECT 0.0680 0.0770 0.0820 0.0910 ;
  END
END OR2_X2_6T_2F_45CPP_24M0P_30M1P_OF15_24M2P_2MPO_ET_M0

MACRO OR2_X1_6T_2F_45CPP_24M0P_30M1P_OF15_24M2P_2MPO_ET_M0
  CLASS CORE ;
  ORIGIN 0 0 ;
  FOREIGN OR2_X1_6T_2F_45CPP_24M0P_30M1P_OF15_24M2P_2MPO_ET_M0 0 0 ;
  SIZE 0.1800 BY 0.1440 ;
  SYMMETRY X Y ;
  SITE coresite ;
  PIN Z
    DIRECTION OUTPUT ;
    USE SIGNAL ;
    PORT
      LAYER M0 ;
        RECT 0.1250 0.0910 0.1675 0.0770 ;
    END
  END Z
  PIN A1
    DIRECTION INPUT ;
    USE SIGNAL ;
    PORT
      LAYER M0 ;
        RECT 0.0125 0.0430 0.0550 0.0290 ;
    END
  END A1
  PIN A2
    DIRECTION INPUT ;
    USE SIGNAL ;
    PORT
      LAYER M0 ;
        RECT 0.0650 0.0430 0.1675 0.0290 ;
    END
  END A2
  PIN VDD
    DIRECTION INOUT ;
    USE POWER ;
    SHAPE ABUTMENT ;
    PORT
      LAYER M0 ;
        RECT 0.0000 0.1260 0.1800 0.1620 ;
    END
  END VDD
  PIN VSS
    DIRECTION INOUT ;
    USE GROUND ;
    SHAPE ABUTMENT ;
    PORT
      LAYER M0 ;
        RECT 0.0000 -0.0180 0.1800 0.0180 ;
    END
  END VSS
  OBS
      LAYER M1 ;
        RECT 0.0675 0.1200 0.0825 0.0240 ;
      LAYER M0 ;
        RECT 0.0125 0.1010 0.1450 0.1150 ;
        RECT 0.0575 0.0530 0.1000 0.0670 ;
      LAYER V0 ;
        RECT 0.0680 0.0530 0.0820 0.0670 ;
        RECT 0.0680 0.1010 0.0820 0.1150 ;
  END
END OR2_X1_6T_2F_45CPP_24M0P_30M1P_OF15_24M2P_2MPO_ET_M0

MACRO AND2_X1_6T_2F_45CPP_24M0P_30M1P_OF15_24M2P_2MPO_ET_M0
  CLASS CORE ;
  ORIGIN 0 0 ;
  FOREIGN AND2_X1_6T_2F_45CPP_24M0P_30M1P_OF15_24M2P_2MPO_ET_M0 0 0 ;
  SIZE 0.1800 BY 0.1440 ;
  SYMMETRY X Y ;
  SITE coresite ;
  PIN A1
    DIRECTION INPUT ;
    USE SIGNAL ;
    PORT
      LAYER M0 ;
        RECT 0.0125 0.0670 0.1150 0.0530 ;
    END
  END A1
  PIN Z
    DIRECTION OUTPUT ;
    USE SIGNAL ;
    PORT
      LAYER M0 ;
        RECT 0.1250 0.1150 0.1675 0.1010 ;
    END
  END Z
  PIN A2
    DIRECTION INPUT ;
    USE SIGNAL ;
    PORT
      LAYER M0 ;
        RECT 0.0650 0.0430 0.1675 0.0290 ;
    END
  END A2
  PIN VDD
    DIRECTION INOUT ;
    USE POWER ;
    SHAPE ABUTMENT ;
    PORT
      LAYER M0 ;
        RECT 0.0000 0.1260 0.1800 0.1620 ;
    END
  END VDD
  PIN VSS
    DIRECTION INOUT ;
    USE GROUND ;
    SHAPE ABUTMENT ;
    PORT
      LAYER M0 ;
        RECT 0.0000 -0.0180 0.1800 0.0180 ;
    END
  END VSS
  OBS
      LAYER M1 ;
        RECT 0.0375 0.1200 0.0525 0.0240 ;
      LAYER M0 ;
        RECT 0.0350 0.0770 0.1450 0.0910 ;
        RECT 0.0125 0.0290 0.0550 0.0430 ;
      LAYER V0 ;
        RECT 0.0380 0.0290 0.0520 0.0430 ;
        RECT 0.0380 0.0770 0.0520 0.0910 ;
  END
END AND2_X1_6T_2F_45CPP_24M0P_30M1P_OF15_24M2P_2MPO_ET_M0

MACRO AND2_X2_6T_2F_45CPP_24M0P_30M1P_OF15_24M2P_2MPO_ET_M0
  CLASS CORE ;
  ORIGIN 0 0 ;
  FOREIGN AND2_X2_6T_2F_45CPP_24M0P_30M1P_OF15_24M2P_2MPO_ET_M0 0 0 ;
  SIZE 0.2250 BY 0.1440 ;
  SYMMETRY X Y ;
  SITE coresite ;
  PIN A1
    DIRECTION INPUT ;
    USE SIGNAL ;
    PORT
      LAYER M0 ;
        RECT 0.0125 0.0670 0.1150 0.0530 ;
    END
  END A1
  PIN Z
    DIRECTION OUTPUT ;
    USE SIGNAL ;
    PORT
      LAYER M0 ;
        RECT 0.1250 0.1150 0.2125 0.1010 ;
    END
  END Z
  PIN A2
    DIRECTION INPUT ;
    USE SIGNAL ;
    PORT
      LAYER M0 ;
        RECT 0.0650 0.0430 0.1750 0.0290 ;
    END
  END A2
  PIN VDD
    DIRECTION INOUT ;
    USE POWER ;
    SHAPE ABUTMENT ;
    PORT
      LAYER M0 ;
        RECT 0.0000 0.1260 0.2250 0.1620 ;
    END
  END VDD
  PIN VSS
    DIRECTION INOUT ;
    USE GROUND ;
    SHAPE ABUTMENT ;
    PORT
      LAYER M0 ;
        RECT 0.0000 -0.0180 0.2250 0.0180 ;
    END
  END VSS
  OBS
      LAYER M1 ;
        RECT 0.0375 0.1200 0.0525 0.0240 ;
      LAYER M0 ;
        RECT 0.0350 0.0770 0.1900 0.0910 ;
        RECT 0.0125 0.0290 0.0550 0.0430 ;
      LAYER V0 ;
        RECT 0.0380 0.0290 0.0520 0.0430 ;
        RECT 0.0380 0.0770 0.0520 0.0910 ;
  END
END AND2_X2_6T_2F_45CPP_24M0P_30M1P_OF15_24M2P_2MPO_ET_M0
